# TR-1um cell library — generated by $APRTOOLS/apr/mklef.py
# source: TR-1um_STDCELL.gds

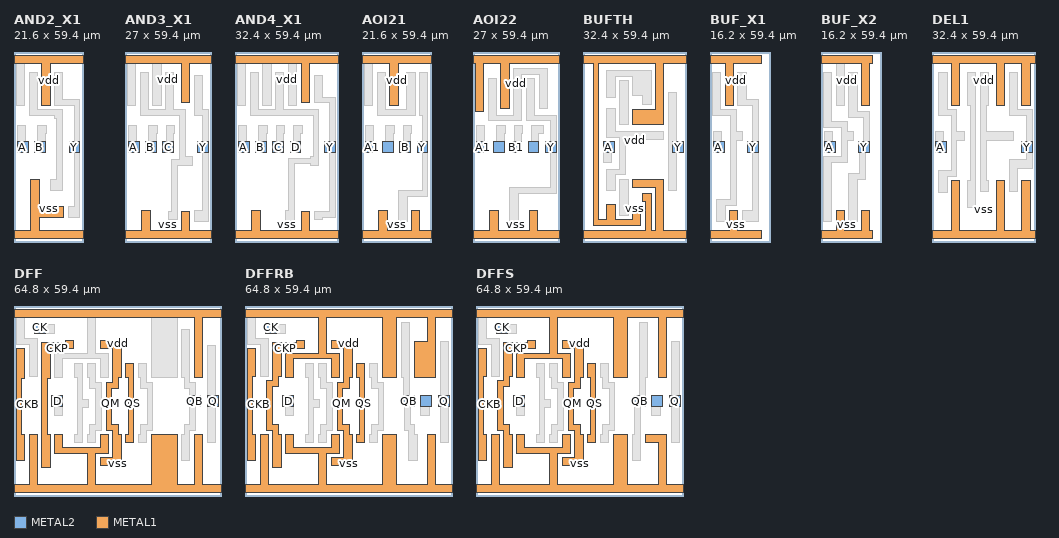
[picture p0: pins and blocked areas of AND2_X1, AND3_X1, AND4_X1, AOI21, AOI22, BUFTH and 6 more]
MACRO AND2_X1
  CLASS CORE ;
  FOREIGN AND2_X1 -0.000 -0.000 ;
  ORIGIN 0.000 0.000 ;
  SIZE 21.600 BY 59.400 ;
  SITE TR1UM ;
  SYMMETRY X Y ;
  PIN A
    DIRECTION INOUT ;
    USE SIGNAL ;
    PORT
      LAYER METAL2 ;
        RECT 1.000 28.000 4.400 31.400 ;
    END
  END A
  PIN B
    DIRECTION INOUT ;
    USE SIGNAL ;
    PORT
      LAYER METAL2 ;
        RECT 6.400 28.000 9.800 31.400 ;
    END
  END B
  PIN Y
    DIRECTION INOUT ;
    USE SIGNAL ;
    PORT
      LAYER METAL2 ;
        RECT 17.200 28.000 20.600 31.400 ;
    END
  END Y
  PIN vdd
    DIRECTION INOUT ;
    USE POWER ;
    SHAPE ABUTMENT ;
    PORT
      LAYER METAL1 ;
        POLYGON 11.300 42.700 11.300 55.700 21.600 55.700 21.600 58.300 0.000 58.300 0.000 55.700 8.700 55.700 8.700 42.700 ;
    END
  END vdd
  PIN vss
    DIRECTION INOUT ;
    USE GROUND ;
    SHAPE ABUTMENT ;
    PORT
      LAYER METAL1 ;
        POLYGON 0.000 1.100 21.600 1.100 21.600 3.700 7.900 3.700 7.900 7.700 15.500 7.700 15.500 11.100 7.900 11.100 7.900 19.600 5.300 19.600 5.300 3.700 0.000 3.700 ;
    END
  END vss
  OBS
    LAYER METAL1 ;
      RECT 0.700 42.700 3.300 55.700 ;
      POLYGON 20.600 44.600 15.300 44.600 15.300 52.900 12.700 52.900 12.700 42.700 18.800 42.700 18.800 31.400 20.600 31.400 ;
      POLYGON 15.200 41.300 7.300 41.300 7.300 52.900 4.700 52.900 4.700 39.500 12.600 39.500 12.600 38.700 13.400 38.700 13.400 19.600 11.500 19.600 11.500 16.200 15.200 16.200 ;
      POLYGON 9.800 33.900 10.100 33.900 10.100 36.500 7.500 36.500 7.500 31.400 9.800 31.400 ;
      RECT 1.000 31.400 3.600 36.500 ;
      POLYGON 16.900 11.100 16.900 7.700 20.600 7.700 20.600 28.000 18.800 28.000 18.800 11.100 ;
  END
END AND2_X1

MACRO AND3_X1
  CLASS CORE ;
  FOREIGN AND3_X1 -0.000 -0.000 ;
  ORIGIN 0.000 0.000 ;
  SIZE 27.000 BY 59.400 ;
  SITE TR1UM ;
  SYMMETRY X Y ;
  PIN A
    DIRECTION INOUT ;
    USE SIGNAL ;
    PORT
      LAYER METAL2 ;
        RECT 1.000 28.000 4.400 31.400 ;
    END
  END A
  PIN B
    DIRECTION INOUT ;
    USE SIGNAL ;
    PORT
      LAYER METAL2 ;
        RECT 6.400 28.000 9.800 31.400 ;
    END
  END B
  PIN C
    DIRECTION INOUT ;
    USE SIGNAL ;
    PORT
      LAYER METAL2 ;
        RECT 11.800 28.000 15.200 31.400 ;
    END
  END C
  PIN Y
    DIRECTION INOUT ;
    USE SIGNAL ;
    PORT
      LAYER METAL2 ;
        RECT 22.600 28.000 26.000 31.400 ;
    END
  END Y
  PIN vdd
    DIRECTION INOUT ;
    USE POWER ;
    SHAPE ABUTMENT ;
    PORT
      LAYER METAL1 ;
        POLYGON 20.300 43.500 20.300 55.700 27.000 55.700 27.000 58.300 0.000 58.300 0.000 55.700 17.700 55.700 17.700 43.500 ;
    END
  END vdd
  PIN vss
    DIRECTION INOUT ;
    USE GROUND ;
    SHAPE ABUTMENT ;
    PORT
      LAYER METAL1 ;
        POLYGON 0.000 1.100 27.000 1.100 27.000 3.700 20.300 3.700 20.300 9.500 17.700 9.500 17.700 3.700 7.900 3.700 7.900 9.900 5.300 9.900 5.300 3.700 0.000 3.700 ;
    END
  END vss
  OBS
    LAYER METAL1 ;
      RECT 8.700 42.700 11.300 55.700 ;
      RECT 0.700 42.700 3.300 55.700 ;
      POLYGON 16.300 24.000 21.200 24.000 21.200 26.600 18.900 26.600 18.900 41.300 15.300 41.300 15.300 52.900 12.700 52.900 12.700 41.300 7.300 41.300 7.300 52.900 4.700 52.900 4.700 39.500 17.100 39.500 17.100 25.800 14.500 25.800 14.500 9.500 13.700 9.500 13.700 6.900 16.300 6.900 ;
      POLYGON 26.000 41.300 24.300 41.300 24.300 52.100 21.700 52.100 21.700 39.500 24.200 39.500 24.200 31.400 26.000 31.400 ;
      RECT 1.000 31.400 3.600 36.500 ;
      POLYGON 9.800 33.900 10.100 33.900 10.100 36.500 7.500 36.500 7.500 31.400 9.800 31.400 ;
      POLYGON 15.200 33.900 15.500 33.900 15.500 36.500 12.900 36.500 12.900 31.400 15.200 31.400 ;
      POLYGON 21.700 9.900 21.700 6.500 26.000 6.500 26.000 28.000 24.200 28.000 24.200 9.900 ;
  END
END AND3_X1

MACRO AND4_X1
  CLASS CORE ;
  FOREIGN AND4_X1 -0.000 -0.000 ;
  ORIGIN 0.000 0.000 ;
  SIZE 32.400 BY 59.400 ;
  SITE TR1UM ;
  SYMMETRY X Y ;
  PIN A
    DIRECTION INOUT ;
    USE SIGNAL ;
    PORT
      LAYER METAL2 ;
        RECT 1.000 28.000 4.400 31.400 ;
    END
  END A
  PIN B
    DIRECTION INOUT ;
    USE SIGNAL ;
    PORT
      LAYER METAL2 ;
        RECT 6.400 28.000 9.800 31.400 ;
    END
  END B
  PIN C
    DIRECTION INOUT ;
    USE SIGNAL ;
    PORT
      LAYER METAL2 ;
        RECT 11.800 28.000 15.200 31.400 ;
    END
  END C
  PIN D
    DIRECTION INOUT ;
    USE SIGNAL ;
    PORT
      LAYER METAL2 ;
        RECT 17.200 28.000 20.600 31.400 ;
    END
  END D
  PIN Y
    DIRECTION INOUT ;
    USE SIGNAL ;
    PORT
      LAYER METAL2 ;
        RECT 28.000 28.000 31.400 31.400 ;
    END
  END Y
  PIN vdd
    DIRECTION INOUT ;
    USE POWER ;
    SHAPE ABUTMENT ;
    PORT
      LAYER METAL1 ;
        POLYGON 23.400 43.500 23.400 55.700 32.400 55.700 32.400 58.300 0.000 58.300 0.000 55.700 20.800 55.700 20.800 43.500 ;
    END
  END vdd
  PIN vss
    DIRECTION INOUT ;
    USE GROUND ;
    SHAPE ABUTMENT ;
    PORT
      LAYER METAL1 ;
        POLYGON 0.000 1.100 32.400 1.100 32.400 3.700 23.400 3.700 23.400 9.500 20.800 9.500 20.800 3.700 7.900 3.700 7.900 9.900 5.300 9.900 5.300 3.700 0.000 3.700 ;
    END
  END vss
  OBS
    LAYER METAL1 ;
      RECT 16.700 42.700 19.300 55.700 ;
      RECT 0.700 42.700 3.300 55.700 ;
      RECT 8.700 42.700 11.300 55.700 ;
      POLYGON 15.900 6.500 18.500 6.500 18.500 24.400 23.600 24.400 23.600 24.000 26.200 24.000 26.200 41.300 15.300 41.300 15.300 52.900 12.700 52.900 12.700 41.300 7.300 41.300 7.300 52.900 4.700 52.900 4.700 39.500 24.400 39.500 24.400 26.600 23.600 26.600 23.600 26.200 16.700 26.200 16.700 9.900 15.900 9.900 ;
      POLYGON 31.400 45.300 27.400 45.300 27.400 52.100 24.800 52.100 24.800 43.500 29.600 43.500 29.600 31.400 31.400 31.400 ;
      POLYGON 20.600 33.900 21.000 33.900 21.000 36.500 18.300 36.500 18.300 31.400 20.600 31.400 ;
      POLYGON 15.200 33.900 15.500 33.900 15.500 36.500 12.900 36.500 12.900 31.400 15.200 31.400 ;
      RECT 1.000 31.400 3.600 36.500 ;
      POLYGON 9.800 33.900 10.100 33.900 10.100 36.500 7.500 36.500 7.500 31.400 9.800 31.400 ;
      POLYGON 24.800 6.900 27.400 6.900 27.400 7.700 31.400 7.700 31.400 28.000 29.600 28.000 29.600 9.500 24.800 9.500 ;
  END
END AND4_X1

MACRO AOI21
  CLASS CORE ;
  FOREIGN AOI21 -0.000 -0.000 ;
  ORIGIN 0.000 0.000 ;
  SIZE 21.600 BY 59.400 ;
  SITE TR1UM ;
  SYMMETRY X Y ;
  PIN A1
    DIRECTION INOUT ;
    USE SIGNAL ;
    PORT
      LAYER METAL2 ;
        RECT 1.000 28.000 4.400 31.400 ;
    END
  END A1
  PIN A2
    DIRECTION INOUT ;
    USE SIGNAL ;
    PORT
      LAYER METAL2 ;
        RECT 6.400 28.000 9.800 31.400 ;
    END
  END A2
  PIN B
    DIRECTION INOUT ;
    USE SIGNAL ;
    PORT
      LAYER METAL2 ;
        RECT 11.800 28.000 15.200 31.400 ;
    END
  END B
  PIN Y
    DIRECTION INOUT ;
    USE SIGNAL ;
    PORT
      LAYER METAL2 ;
        RECT 17.200 28.000 20.600 31.400 ;
    END
  END Y
  PIN vdd
    DIRECTION INOUT ;
    USE POWER ;
    SHAPE ABUTMENT ;
    PORT
      LAYER METAL1 ;
        POLYGON 11.300 42.700 11.300 55.700 21.600 55.700 21.600 58.300 0.000 58.300 0.000 55.700 8.700 55.700 8.700 42.700 ;
    END
  END vdd
  PIN vss
    DIRECTION INOUT ;
    USE GROUND ;
    SHAPE ABUTMENT ;
    PORT
      LAYER METAL1 ;
        POLYGON 0.000 1.100 21.600 1.100 21.600 3.700 18.100 3.700 18.100 9.900 15.500 9.900 15.500 3.700 7.900 3.700 7.900 9.900 5.300 9.900 5.300 3.700 0.000 3.700 ;
    END
  END vss
  OBS
    LAYER METAL1 ;
      RECT 0.700 42.700 3.300 55.700 ;
      POLYGON 20.600 52.900 18.000 52.900 18.000 39.500 18.800 39.500 18.800 31.400 20.600 31.400 ;
      POLYGON 16.600 52.900 14.000 52.900 14.000 41.300 7.300 41.300 7.300 52.900 4.700 52.900 4.700 39.500 16.600 39.500 ;
      POLYGON 15.200 33.900 15.500 33.900 15.500 36.500 12.900 36.500 12.900 31.400 15.200 31.400 ;
      RECT 1.000 31.400 3.600 36.500 ;
      POLYGON 9.800 33.900 10.100 33.900 10.100 36.500 7.500 36.500 7.500 31.400 9.800 31.400 ;
      POLYGON 11.500 16.000 11.500 6.500 14.100 6.500 14.100 14.200 20.600 14.200 20.600 28.000 18.800 28.000 18.800 16.000 ;
  END
END AOI21

MACRO AOI22
  CLASS CORE ;
  FOREIGN AOI22 -0.000 -0.000 ;
  ORIGIN 0.000 0.000 ;
  SIZE 27.000 BY 59.400 ;
  SITE TR1UM ;
  SYMMETRY X Y ;
  PIN A1
    DIRECTION INOUT ;
    USE SIGNAL ;
    PORT
      LAYER METAL2 ;
        RECT 1.000 28.000 4.400 31.400 ;
    END
  END A1
  PIN A2
    DIRECTION INOUT ;
    USE SIGNAL ;
    PORT
      LAYER METAL2 ;
        RECT 6.400 28.000 9.800 31.400 ;
    END
  END A2
  PIN B1
    DIRECTION INOUT ;
    USE SIGNAL ;
    PORT
      LAYER METAL2 ;
        RECT 11.800 28.000 15.200 31.400 ;
    END
  END B1
  PIN B2
    DIRECTION INOUT ;
    USE SIGNAL ;
    PORT
      LAYER METAL2 ;
        RECT 17.200 28.000 20.600 31.400 ;
    END
  END B2
  PIN Y
    DIRECTION INOUT ;
    USE SIGNAL ;
    PORT
      LAYER METAL2 ;
        RECT 22.600 28.000 26.000 31.400 ;
    END
  END Y
  PIN vdd
    DIRECTION INOUT ;
    USE POWER ;
    SHAPE ABUTMENT ;
    PORT
      LAYER METAL1 ;
        POLYGON 3.300 40.900 3.300 55.700 8.700 55.700 8.700 41.700 11.300 41.700 11.300 55.700 27.000 55.700 27.000 58.300 0.000 58.300 0.000 55.700 0.700 55.700 0.700 40.900 ;
    END
  END vdd
  PIN vss
    DIRECTION INOUT ;
    USE GROUND ;
    SHAPE ABUTMENT ;
    PORT
      LAYER METAL1 ;
        POLYGON 0.000 1.100 27.000 1.100 27.000 3.700 20.300 3.700 20.300 9.900 17.700 9.900 17.700 3.700 7.900 3.700 7.900 9.900 5.300 9.900 5.300 3.700 0.000 3.700 ;
    END
  END vss
  OBS
    LAYER METAL1 ;
      POLYGON 15.300 52.500 20.700 52.500 20.700 41.700 23.300 41.700 23.300 54.300 12.700 54.300 12.700 39.700 7.300 39.700 7.300 51.100 4.700 51.100 4.700 37.900 15.300 37.900 ;
      POLYGON 16.700 51.100 16.700 37.900 24.200 37.900 24.200 31.400 26.000 31.400 26.000 39.700 19.300 39.700 19.300 51.100 ;
      POLYGON 20.600 33.900 22.100 33.900 22.100 36.500 18.300 36.500 18.300 31.400 20.600 31.400 ;
      RECT 1.000 31.400 3.600 36.500 ;
      POLYGON 9.800 33.900 10.100 33.900 10.100 36.500 7.500 36.500 7.500 31.400 9.800 31.400 ;
      POLYGON 15.200 33.900 15.500 33.900 15.500 36.500 12.900 36.500 12.900 31.400 15.200 31.400 ;
      POLYGON 11.500 17.000 11.500 6.500 14.100 6.500 14.100 15.200 26.000 15.200 26.000 28.000 24.200 28.000 24.200 17.000 ;
  END
END AOI22

MACRO BUFTH
  CLASS CORE ;
  FOREIGN BUFTH -0.000 -0.000 ;
  ORIGIN 0.000 0.000 ;
  SIZE 32.400 BY 59.400 ;
  SITE TR1UM ;
  SYMMETRY X Y ;
  PIN A
    DIRECTION INOUT ;
    USE SIGNAL ;
    PORT
      LAYER METAL2 ;
        RECT 6.400 28.000 9.800 31.400 ;
    END
  END A
  PIN Y
    DIRECTION INOUT ;
    USE SIGNAL ;
    PORT
      LAYER METAL2 ;
        RECT 28.000 28.000 31.400 31.400 ;
    END
  END Y
  PIN vdd
    DIRECTION INOUT ;
    USE POWER ;
    SHAPE ABUTMENT ;
    PORT
      LAYER METAL1 ;
        POLYGON 18.100 5.100 18.100 10.900 15.500 10.900 15.500 6.900 10.100 6.900 10.100 11.700 7.500 11.700 7.500 6.900 5.000 6.900 5.000 55.700 22.700 55.700 22.700 41.300 15.500 41.300 15.500 36.600 25.300 36.600 25.300 55.700 32.400 55.700 32.400 58.300 0.000 58.300 0.000 55.700 3.200 55.700 3.200 5.100 ;
    END
  END vdd
  PIN vss
    DIRECTION INOUT ;
    USE GROUND ;
    SHAPE ABUTMENT ;
    PORT
      LAYER METAL1 ;
        POLYGON 0.000 1.100 32.400 1.100 32.400 3.700 25.300 3.700 25.300 19.600 15.500 19.600 15.500 17.000 22.700 17.000 22.700 3.700 21.300 3.700 21.300 15.300 18.700 15.300 18.700 12.700 19.500 12.700 19.500 3.700 0.000 3.700 ;
    END
  END vss
  OBS
    LAYER METAL1 ;
      POLYGON 21.300 53.600 7.500 53.600 7.500 45.300 10.100 45.300 10.100 51.800 15.500 51.800 15.500 45.700 18.700 45.700 18.700 43.100 21.300 43.100 ;
      RECT 11.500 36.600 14.100 50.400 ;
      POLYGON 29.300 46.800 26.700 46.800 26.700 16.200 29.300 16.200 29.300 28.000 28.000 28.000 28.000 31.400 29.300 31.400 ;
      POLYGON 10.100 21.000 13.200 21.000 13.200 32.000 25.300 32.000 25.300 34.600 10.100 34.600 10.100 41.700 7.500 41.700 7.500 32.800 11.400 32.800 11.400 22.800 7.500 22.800 7.500 16.200 10.100 16.200 ;
      RECT 6.400 25.000 9.000 28.000 ;
      RECT 11.500 8.300 14.100 19.600 ;
  END
END BUFTH

MACRO BUF_X1
  CLASS CORE ;
  FOREIGN BUF_X1 -0.000 -0.000 ;
  ORIGIN 0.000 0.000 ;
  SIZE 16.200 BY 59.400 ;
  SITE TR1UM ;
  SYMMETRY X Y ;
  PIN A
    DIRECTION INOUT ;
    USE SIGNAL ;
    PORT
      LAYER METAL2 ;
        RECT 1.000 28.000 4.400 31.400 ;
    END
  END A
  PIN Y
    DIRECTION INOUT ;
    USE SIGNAL ;
    PORT
      LAYER METAL2 ;
        RECT 11.800 28.000 15.200 31.400 ;
    END
  END Y
  PIN vdd
    DIRECTION INOUT ;
    USE POWER ;
    SHAPE ABUTMENT ;
    PORT
      LAYER METAL1 ;
        POLYGON 7.300 42.700 7.300 55.700 16.200 55.700 16.200 58.300 0.000 58.300 0.000 55.700 4.700 55.700 4.700 42.700 ;
    END
  END vdd
  PIN vss
    DIRECTION INOUT ;
    USE GROUND ;
    SHAPE ABUTMENT ;
    PORT
      LAYER METAL1 ;
        POLYGON 0.000 1.100 16.200 1.100 16.200 3.700 8.700 3.700 8.700 9.900 6.100 9.900 6.100 3.700 0.000 3.700 ;
    END
  END vss
  OBS
    LAYER METAL1 ;
      POLYGON 15.200 44.500 11.300 44.500 11.300 52.900 8.700 52.900 8.700 42.700 13.400 42.700 13.400 31.400 15.200 31.400 ;
      POLYGON 4.700 11.500 8.300 11.500 8.300 31.800 10.100 31.800 10.100 34.400 8.300 34.400 8.300 41.300 3.300 41.300 3.300 52.900 0.700 52.900 0.700 39.500 6.500 39.500 6.500 13.300 2.100 13.300 2.100 6.500 4.700 6.500 ;
      RECT 1.000 31.400 3.600 34.400 ;
      POLYGON 10.100 9.900 10.100 6.500 15.200 6.500 15.200 28.000 13.400 28.000 13.400 9.900 ;
  END
END BUF_X1

MACRO BUF_X2
  CLASS CORE ;
  FOREIGN BUF_X2 -0.000 -0.000 ;
  ORIGIN 0.000 0.000 ;
  SIZE 16.200 BY 59.400 ;
  SITE TR1UM ;
  SYMMETRY X Y ;
  PIN A
    DIRECTION INOUT ;
    USE SIGNAL ;
    PORT
      LAYER METAL2 ;
        RECT 1.000 28.000 4.400 31.400 ;
    END
  END A
  PIN Y
    DIRECTION INOUT ;
    USE SIGNAL ;
    PORT
      LAYER METAL2 ;
        RECT 11.800 28.000 15.200 31.400 ;
    END
  END Y
  PIN vdd
    DIRECTION INOUT ;
    USE POWER ;
    SHAPE ABUTMENT ;
    PORT
      LAYER METAL1 ;
        POLYGON 15.300 42.700 15.300 55.700 16.200 55.700 16.200 58.300 0.000 58.300 0.000 55.700 12.700 55.700 12.700 42.700 ;
    END
  END vdd
  PIN vss
    DIRECTION INOUT ;
    USE GROUND ;
    SHAPE ABUTMENT ;
    PORT
      LAYER METAL1 ;
        POLYGON 0.000 1.100 16.200 1.100 16.200 3.700 15.300 3.700 15.300 9.900 12.700 9.900 12.700 3.700 7.300 3.700 7.300 9.900 4.700 9.900 4.700 3.700 0.000 3.700 ;
    END
  END vss
  OBS
    LAYER METAL1 ;
      RECT 4.700 42.700 7.300 55.700 ;
      POLYGON 15.200 40.800 11.300 40.800 11.300 52.900 8.700 52.900 8.700 39.000 13.400 39.000 13.400 31.400 15.200 31.400 ;
      POLYGON 3.300 24.800 8.300 24.800 8.300 31.800 10.100 31.800 10.100 34.400 8.300 34.400 8.300 37.600 3.300 37.600 3.300 52.900 0.700 52.900 0.700 35.800 6.500 35.800 6.500 26.600 0.700 26.600 0.700 6.500 3.300 6.500 ;
      RECT 1.000 31.400 3.600 34.400 ;
      POLYGON 8.700 21.400 8.700 6.500 11.300 6.500 11.300 19.600 13.800 19.600 13.800 28.000 12.000 28.000 12.000 21.400 ;
  END
END BUF_X2

MACRO DEL1
  CLASS CORE ;
  FOREIGN DEL1 -0.000 -0.000 ;
  ORIGIN 0.000 0.000 ;
  SIZE 32.400 BY 59.400 ;
  SITE TR1UM ;
  SYMMETRY X Y ;
  PIN A
    DIRECTION INOUT ;
    USE SIGNAL ;
    PORT
      LAYER METAL2 ;
        RECT 1.000 28.000 4.400 31.400 ;
    END
  END A
  PIN Y
    DIRECTION INOUT ;
    USE SIGNAL ;
    PORT
      LAYER METAL2 ;
        RECT 28.000 28.000 31.400 31.400 ;
    END
  END Y
  PIN vdd
    DIRECTION INOUT ;
    USE POWER ;
    SHAPE ABUTMENT ;
    PORT
      LAYER METAL1 ;
        POLYGON 8.700 55.700 20.100 55.700 20.100 42.700 22.700 42.700 22.700 55.700 28.100 55.700 28.100 42.700 30.700 42.700 30.700 55.700 32.400 55.700 32.400 58.300 0.000 58.300 0.000 55.700 6.100 55.700 6.100 42.700 8.700 42.700 ;
    END
  END vdd
  PIN vss
    DIRECTION INOUT ;
    USE GROUND ;
    SHAPE ABUTMENT ;
    PORT
      LAYER METAL1 ;
        POLYGON 32.400 3.700 30.700 3.700 30.700 19.100 28.100 19.100 28.100 3.700 22.700 3.700 22.700 19.100 20.100 19.100 20.100 3.700 8.700 3.700 8.700 19.100 6.100 19.100 6.100 3.700 0.000 3.700 0.000 1.100 32.400 1.100 ;
    END
  END vss
  OBS
    LAYER METAL1 ;
      POLYGON 31.400 41.300 26.700 41.300 26.700 52.900 24.100 52.900 24.100 39.500 29.600 39.500 29.600 31.400 31.400 31.400 ;
      POLYGON 13.700 52.900 11.100 52.900 11.100 42.700 11.900 42.700 11.900 19.100 11.100 19.100 11.100 10.700 13.700 10.700 ;
      POLYGON 17.700 19.100 16.900 19.100 16.900 31.800 25.500 31.800 25.500 34.400 16.900 34.400 16.900 42.700 17.700 42.700 17.700 52.900 15.100 52.900 15.100 15.700 17.700 15.700 ;
      POLYGON 4.700 20.500 7.800 20.500 7.800 31.800 10.100 31.800 10.100 34.400 7.800 34.400 7.800 41.300 4.700 41.300 4.700 52.900 2.100 52.900 2.100 39.500 6.000 39.500 6.000 22.300 2.100 22.300 2.100 15.500 4.700 15.500 ;
      RECT 1.000 31.400 3.600 34.400 ;
      POLYGON 24.100 25.800 24.100 15.700 26.700 15.700 26.700 22.900 31.400 22.900 31.400 28.000 29.600 28.000 29.600 25.800 ;
  END
END DEL1

MACRO DFF
  CLASS CORE ;
  FOREIGN DFF -0.000 -0.000 ;
  ORIGIN 0.000 0.000 ;
  SIZE 64.800 BY 59.400 ;
  SITE TR1UM ;
  SYMMETRY X Y ;
  PIN CK
    DIRECTION INOUT ;
    USE SIGNAL ;
    PORT
      LAYER METAL2 ;
        RECT 6.400 50.900 9.800 54.300 ;
    END
  END CK
  PIN CKB
    DIRECTION INOUT ;
    USE SIGNAL ;
    PORT
      LAYER METAL1 ;
        POLYGON 3.300 19.200 2.500 19.200 2.500 36.600 3.300 36.600 3.300 46.100 0.700 46.100 0.700 11.200 3.300 11.200 ;
    END
  END CKB
  PIN CKP
    DIRECTION INOUT ;
    USE SIGNAL ;
    PORT
      LAYER METAL1 ;
        POLYGON 11.300 19.200 10.500 19.200 10.500 22.400 10.400 22.400 10.400 34.300 10.500 34.300 10.500 36.600 11.300 36.600 11.300 46.100 18.700 46.100 18.700 48.700 16.100 48.700 16.100 47.900 8.700 47.900 8.700 36.100 8.600 36.100 8.600 20.600 8.700 20.600 8.700 9.000 11.300 9.000 ;
    END
  END CKP
  PIN D
    DIRECTION INOUT ;
    USE SIGNAL ;
    PORT
      LAYER METAL2 ;
        RECT 11.800 27.900 15.200 31.300 ;
    END
  END D
  PIN Q
    DIRECTION INOUT ;
    USE SIGNAL ;
    PORT
      LAYER METAL2 ;
        RECT 60.400 27.900 63.800 31.300 ;
    END
  END Q
  PIN QB
    DIRECTION INOUT ;
    USE SIGNAL ;
    PORT
      LAYER METAL2 ;
        RECT 55.000 27.900 58.400 31.300 ;
    END
  END QB
  PIN QM
    DIRECTION INOUT ;
    USE SIGNAL ;
    PORT
      LAYER METAL1 ;
        POLYGON 29.500 10.200 33.500 10.200 33.500 19.200 32.700 19.200 32.700 22.400 30.600 22.400 30.600 33.700 32.700 33.700 32.700 36.900 33.500 36.900 33.500 47.900 29.500 47.900 29.500 48.700 26.900 48.700 26.900 46.100 30.900 46.100 30.900 35.500 28.800 35.500 28.800 20.600 30.900 20.600 30.900 12.000 26.900 12.000 26.900 9.400 29.500 9.400 ;
    END
  END QM
  PIN QS
    DIRECTION INOUT ;
    USE SIGNAL ;
    PORT
      LAYER METAL1 ;
        POLYGON 37.500 27.700 39.300 27.700 39.300 30.300 37.500 30.300 37.500 41.500 34.900 41.500 34.900 36.900 35.700 36.900 35.700 19.200 34.900 19.200 34.900 16.600 37.500 16.600 ;
    END
  END QS
  PIN vdd
    DIRECTION INOUT ;
    USE POWER ;
    SHAPE ABUTMENT ;
    PORT
      LAYER METAL1 ;
        POLYGON 59.000 36.900 59.000 55.700 64.800 55.700 64.800 58.300 0.000 58.300 0.000 55.700 56.400 55.700 56.400 36.900 ;
    END
  END vdd
  PIN vss
    DIRECTION INOUT ;
    USE GROUND ;
    SHAPE ABUTMENT ;
    PORT
      LAYER METAL1 ;
        POLYGON 0.000 1.100 64.800 1.100 64.800 3.700 59.000 3.700 59.000 19.200 56.400 19.200 56.400 3.700 51.000 3.700 51.000 19.200 42.900 19.200 42.900 3.700 25.500 3.700 25.500 13.400 29.500 13.400 29.500 19.200 26.900 19.200 26.900 15.200 15.300 15.200 15.300 19.200 12.700 19.200 12.700 13.400 22.900 13.400 22.900 3.700 7.300 3.700 7.300 19.200 4.700 19.200 4.700 3.700 0.000 3.700 ;
    END
  END vss
  OBS
    LAYER METAL1 ;
      RECT 42.900 36.900 51.000 55.700 ;
      POLYGON 7.300 49.300 3.300 49.300 3.300 55.700 0.700 55.700 0.700 47.500 4.700 47.500 4.700 37.400 7.300 37.400 ;
      POLYGON 15.300 42.900 26.900 42.900 26.900 36.900 29.500 36.900 29.500 44.700 25.500 44.700 25.500 55.700 22.900 55.700 22.900 44.700 12.700 44.700 12.700 36.900 15.300 36.900 ;
      RECT 9.800 50.900 12.800 53.500 ;
      POLYGON 56.800 35.500 55.000 35.500 55.000 52.000 52.400 52.000 52.400 36.900 53.200 36.900 53.200 33.700 55.000 33.700 55.000 31.300 56.800 31.300 ;
      RECT 60.400 31.300 63.000 47.000 ;
      POLYGON 21.500 27.700 23.200 27.700 23.200 30.300 21.500 30.300 21.500 41.500 18.900 41.500 18.900 36.900 19.700 36.900 19.700 19.200 18.900 19.200 18.900 16.600 21.500 16.600 ;
      POLYGON 25.500 20.600 27.400 20.600 27.400 35.500 25.500 35.500 25.500 41.500 22.900 41.500 22.900 36.900 23.700 36.900 23.700 33.700 25.600 33.700 25.600 22.400 23.700 22.400 23.700 19.200 22.900 19.200 22.900 16.600 25.500 16.600 ;
      POLYGON 41.500 20.600 43.400 20.600 43.400 35.500 41.500 35.500 41.500 41.500 38.900 41.500 38.900 36.900 39.700 36.900 39.700 33.700 41.600 33.700 41.600 22.400 39.700 22.400 39.700 19.200 38.900 19.200 38.900 16.600 41.500 16.600 ;
      RECT 12.600 25.100 15.200 27.900 ;
      POLYGON 53.200 22.400 53.200 19.200 52.400 19.200 52.400 11.200 55.000 11.200 55.000 20.600 56.800 20.600 56.800 27.900 55.000 27.900 55.000 22.400 ;
      RECT 60.400 16.600 63.000 27.900 ;
  END
END DFF

MACRO DFFRB
  CLASS CORE ;
  FOREIGN DFFRB -0.000 -0.000 ;
  ORIGIN 0.000 0.000 ;
  SIZE 64.800 BY 59.400 ;
  SITE TR1UM ;
  SYMMETRY X Y ;
  PIN CK
    DIRECTION INOUT ;
    USE SIGNAL ;
    PORT
      LAYER METAL2 ;
        RECT 6.400 50.900 9.800 54.300 ;
    END
  END CK
  PIN CKB
    DIRECTION INOUT ;
    USE SIGNAL ;
    PORT
      LAYER METAL1 ;
        POLYGON 3.300 19.200 2.500 19.200 2.500 37.500 3.300 37.500 3.300 46.100 0.700 46.100 0.700 11.200 3.300 11.200 ;
    END
  END CKB
  PIN CKP
    DIRECTION INOUT ;
    USE SIGNAL ;
    PORT
      LAYER METAL1 ;
        POLYGON 10.500 19.200 10.500 22.400 8.600 22.400 8.600 34.300 10.500 34.300 10.500 37.500 11.300 37.500 11.300 46.100 18.700 46.100 18.700 48.700 16.100 48.700 16.100 47.900 8.700 47.900 8.700 36.100 6.800 36.100 6.800 20.600 8.700 20.600 8.700 9.000 11.300 9.000 11.300 19.200 ;
    END
  END CKP
  PIN D
    DIRECTION INOUT ;
    USE SIGNAL ;
    PORT
      LAYER METAL2 ;
        RECT 11.800 27.900 15.200 31.300 ;
    END
  END D
  PIN Q
    DIRECTION INOUT ;
    USE SIGNAL ;
    PORT
      LAYER METAL2 ;
        RECT 60.400 27.900 63.800 31.300 ;
    END
  END Q
  PIN QB
    DIRECTION INOUT ;
    USE SIGNAL ;
    PORT
      LAYER METAL2 ;
        RECT 49.600 27.900 53.000 31.300 ;
        RECT 49.600 27.900 53.000 31.300 ;
    END
  END QB
  PIN QM
    DIRECTION INOUT ;
    USE SIGNAL ;
    PORT
      LAYER METAL1 ;
        POLYGON 26.900 9.400 29.500 9.400 29.500 10.200 33.500 10.200 33.500 19.200 32.700 19.200 32.700 22.400 30.600 22.400 30.600 33.700 32.700 33.700 32.700 36.900 33.500 36.900 33.500 47.900 29.500 47.900 29.500 48.700 26.900 48.700 26.900 46.100 30.900 46.100 30.900 35.500 28.800 35.500 28.800 20.600 30.900 20.600 30.900 12.000 26.900 12.000 ;
    END
  END QM
  PIN QS
    DIRECTION INOUT ;
    USE SIGNAL ;
    PORT
      LAYER METAL1 ;
        POLYGON 37.500 27.700 39.300 27.700 39.300 30.300 37.500 30.300 37.500 41.500 34.900 41.500 34.900 36.900 35.700 36.900 35.700 19.200 34.900 19.200 34.900 16.600 37.500 16.600 ;
    END
  END QS
  PIN RSTB
    DIRECTION INOUT ;
    USE SIGNAL ;
    PORT
      LAYER METAL2 ;
        RECT 55.000 27.900 58.400 31.300 ;
    END
  END RSTB
  PIN vdd
    DIRECTION INOUT ;
    USE POWER ;
    SHAPE ABUTMENT ;
    PORT
      LAYER METAL1 ;
        POLYGON 57.000 48.400 52.900 48.400 52.900 36.900 59.600 36.900 59.600 55.700 64.800 55.700 64.800 58.300 0.000 58.300 0.000 55.700 22.900 55.700 22.900 44.700 12.700 44.700 12.700 36.900 15.300 36.900 15.300 42.900 26.900 42.900 26.900 36.900 29.500 36.900 29.500 44.700 25.500 44.700 25.500 55.700 42.900 55.700 42.900 36.900 47.500 36.900 47.500 55.700 57.000 55.700 ;
    END
  END vdd
  PIN vss
    DIRECTION INOUT ;
    USE GROUND ;
    SHAPE ABUTMENT ;
    PORT
      LAYER METAL1 ;
        POLYGON 0.000 1.100 64.800 1.100 64.800 3.700 59.600 3.700 59.600 19.200 57.000 19.200 57.000 3.700 47.500 3.700 47.500 19.200 42.900 19.200 42.900 3.700 25.500 3.700 25.500 13.400 29.500 13.400 29.500 19.200 26.900 19.200 26.900 15.200 15.300 15.200 15.300 19.200 12.700 19.200 12.700 13.400 22.900 13.400 22.900 3.700 7.300 3.700 7.300 19.200 4.700 19.200 4.700 3.700 0.000 3.700 ;
    END
  END vss
  OBS
    LAYER METAL1 ;
      POLYGON 7.300 49.300 3.300 49.300 3.300 55.700 0.700 55.700 0.700 47.500 4.700 47.500 4.700 37.500 7.300 37.500 ;
      POLYGON 51.500 54.200 48.900 54.200 48.900 36.900 49.700 36.900 49.700 31.300 51.500 31.300 ;
      RECT 9.800 50.900 12.800 53.500 ;
      RECT 61.000 31.300 63.600 48.400 ;
      POLYGON 21.500 27.700 23.200 27.700 23.200 30.300 21.500 30.300 21.500 41.500 18.900 41.500 18.900 36.900 19.700 36.900 19.700 19.200 18.900 19.200 18.900 16.600 21.500 16.600 ;
      POLYGON 25.500 20.600 27.400 20.600 27.400 35.500 25.500 35.500 25.500 41.500 22.900 41.500 22.900 36.900 23.700 36.900 23.700 33.700 25.600 33.700 25.600 22.400 23.700 22.400 23.700 19.200 22.900 19.200 22.900 16.600 25.500 16.600 ;
      POLYGON 41.500 20.600 43.400 20.600 43.400 35.500 41.500 35.500 41.500 41.500 38.900 41.500 38.900 36.900 39.700 36.900 39.700 33.700 41.600 33.700 41.600 22.400 39.700 22.400 39.700 19.200 38.900 19.200 38.900 16.600 41.500 16.600 ;
      RECT 12.600 25.100 15.200 27.900 ;
      RECT 55.000 25.100 57.600 27.900 ;
      POLYGON 51.200 20.600 51.200 11.200 53.800 11.200 53.800 19.200 53.000 19.200 53.000 22.400 51.600 22.400 51.600 27.900 49.800 27.900 49.800 20.600 ;
      RECT 61.000 16.600 63.600 27.900 ;
  END
END DFFRB

MACRO DFFS
  CLASS CORE ;
  FOREIGN DFFS -0.000 -0.000 ;
  ORIGIN 0.000 0.000 ;
  SIZE 64.800 BY 59.400 ;
  SITE TR1UM ;
  SYMMETRY X Y ;
  PIN CK
    DIRECTION INOUT ;
    USE SIGNAL ;
    PORT
      LAYER METAL2 ;
        RECT 6.400 50.900 9.800 54.300 ;
    END
  END CK
  PIN CKB
    DIRECTION INOUT ;
    USE SIGNAL ;
    PORT
      LAYER METAL1 ;
        POLYGON 3.300 19.200 2.500 19.200 2.500 37.500 3.300 37.500 3.300 46.100 0.700 46.100 0.700 11.200 3.300 11.200 ;
    END
  END CKB
  PIN CKP
    DIRECTION INOUT ;
    USE SIGNAL ;
    PORT
      LAYER METAL1 ;
        POLYGON 11.300 19.200 10.500 19.200 10.500 22.400 8.600 22.400 8.600 34.300 10.500 34.300 10.500 37.500 11.300 37.500 11.300 46.100 18.700 46.100 18.700 48.700 16.100 48.700 16.100 47.900 8.700 47.900 8.700 36.100 6.800 36.100 6.800 20.600 8.700 20.600 8.700 9.000 11.300 9.000 ;
    END
  END CKP
  PIN D
    DIRECTION INOUT ;
    USE SIGNAL ;
    PORT
      LAYER METAL2 ;
        RECT 11.800 27.900 15.200 31.300 ;
    END
  END D
  PIN Q
    DIRECTION INOUT ;
    USE SIGNAL ;
    PORT
      LAYER METAL2 ;
        RECT 60.400 27.900 63.800 31.300 ;
    END
  END Q
  PIN QB
    DIRECTION INOUT ;
    USE SIGNAL ;
    PORT
      LAYER METAL2 ;
        RECT 49.600 27.900 53.000 31.300 ;
        RECT 49.600 27.900 53.000 31.300 ;
    END
  END QB
  PIN QM
    DIRECTION INOUT ;
    USE SIGNAL ;
    PORT
      LAYER METAL1 ;
        POLYGON 29.500 10.200 33.500 10.200 33.500 19.200 32.700 19.200 32.700 22.400 30.600 22.400 30.600 33.700 32.700 33.700 32.700 36.900 33.500 36.900 33.500 47.900 29.500 47.900 29.500 48.700 26.900 48.700 26.900 46.100 30.900 46.100 30.900 35.500 28.800 35.500 28.800 20.600 30.900 20.600 30.900 12.000 26.900 12.000 26.900 9.400 29.500 9.400 ;
    END
  END QM
  PIN QS
    DIRECTION INOUT ;
    USE SIGNAL ;
    PORT
      LAYER METAL1 ;
        POLYGON 37.500 27.700 39.300 27.700 39.300 30.300 37.500 30.300 37.500 41.500 34.900 41.500 34.900 36.900 35.700 36.900 35.700 19.200 34.900 19.200 34.900 16.600 37.500 16.600 ;
    END
  END QS
  PIN SET
    DIRECTION INOUT ;
    USE SIGNAL ;
    PORT
      LAYER METAL2 ;
        RECT 55.000 27.900 58.400 31.300 ;
    END
  END SET
  PIN vdd
    DIRECTION INOUT ;
    USE POWER ;
    SHAPE ABUTMENT ;
    PORT
      LAYER METAL1 ;
        POLYGON 57.000 36.900 59.600 36.900 59.600 55.700 64.800 55.700 64.800 58.300 0.000 58.300 0.000 55.700 22.900 55.700 22.900 44.700 12.700 44.700 12.700 36.900 15.300 36.900 15.300 42.900 26.900 42.900 26.900 36.900 29.500 36.900 29.500 44.700 25.500 44.700 25.500 55.700 42.900 55.700 42.900 36.900 47.500 36.900 47.500 55.700 57.000 55.700 ;
    END
  END vdd
  PIN vss
    DIRECTION INOUT ;
    USE GROUND ;
    SHAPE ABUTMENT ;
    PORT
      LAYER METAL1 ;
        POLYGON 25.500 13.400 29.500 13.400 29.500 19.200 26.900 19.200 26.900 15.200 15.300 15.200 15.300 19.200 12.700 19.200 12.700 13.400 22.900 13.400 22.900 3.700 7.300 3.700 7.300 19.200 4.700 19.200 4.700 3.700 0.000 3.700 0.000 1.100 64.800 1.100 64.800 3.700 59.600 3.700 59.600 19.200 52.900 19.200 52.900 16.600 57.000 16.600 57.000 3.700 47.500 3.700 47.500 19.200 42.900 19.200 42.900 3.700 25.500 3.700 ;
    END
  END vss
  OBS
    LAYER METAL1 ;
      POLYGON 7.300 37.500 7.300 49.300 3.300 49.300 3.300 55.700 0.700 55.700 0.700 47.500 4.700 47.500 4.700 37.500 ;
      POLYGON 52.900 36.900 53.700 36.900 53.700 54.300 51.100 54.300 51.100 31.300 52.900 31.300 ;
      RECT 9.800 50.900 12.800 53.500 ;
      RECT 61.000 31.300 63.600 48.400 ;
      POLYGON 21.500 27.700 23.200 27.700 23.200 30.300 21.500 30.300 21.500 41.500 18.900 41.500 18.900 36.900 19.700 36.900 19.700 19.200 18.900 19.200 18.900 16.600 21.500 16.600 ;
      POLYGON 25.500 20.600 27.400 20.600 27.400 35.500 25.500 35.500 25.500 41.500 22.900 41.500 22.900 36.900 23.700 36.900 23.700 33.700 25.600 33.700 25.600 22.400 23.700 22.400 23.700 19.200 22.900 19.200 22.900 16.600 25.500 16.600 ;
      POLYGON 41.500 20.600 43.400 20.600 43.400 35.500 41.500 35.500 41.500 41.500 38.900 41.500 38.900 36.900 39.700 36.900 39.700 33.700 41.600 33.700 41.600 22.400 39.700 22.400 39.700 19.200 38.900 19.200 38.900 16.600 41.500 16.600 ;
      RECT 55.000 25.100 57.600 27.900 ;
      RECT 12.600 25.100 15.200 27.900 ;
      RECT 61.000 16.600 63.600 27.900 ;
      POLYGON 48.900 19.200 48.900 11.200 51.500 11.200 51.500 27.900 49.700 27.900 49.700 19.200 ;
  END
END DFFS

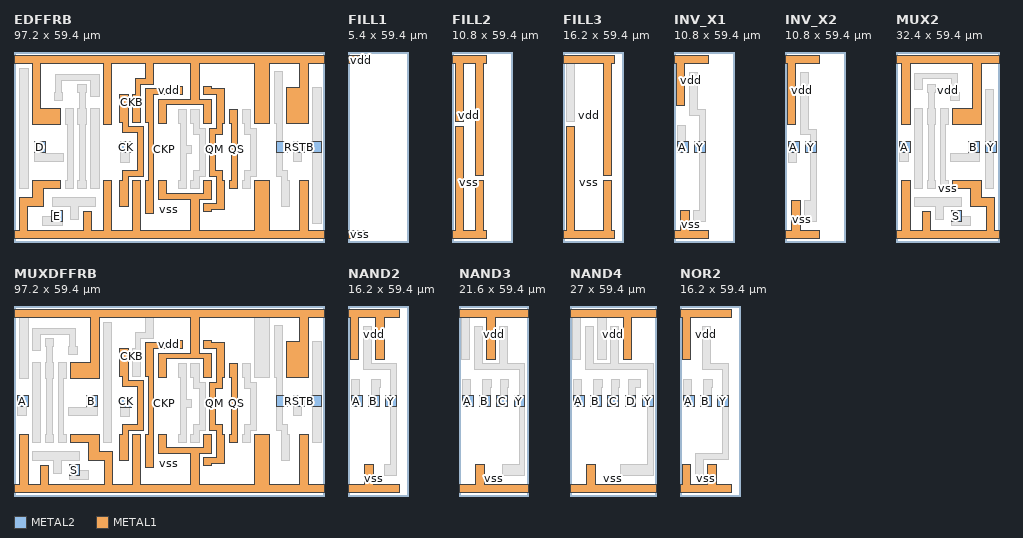
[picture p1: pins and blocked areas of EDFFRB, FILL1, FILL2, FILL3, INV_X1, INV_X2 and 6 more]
MACRO EDFFRB
  CLASS CORE ;
  FOREIGN EDFFRB -0.000 -0.000 ;
  ORIGIN 0.000 0.000 ;
  SIZE 97.200 BY 59.400 ;
  SITE TR1UM ;
  SYMMETRY X Y ;
  PIN CK
    DIRECTION INOUT ;
    USE SIGNAL ;
    PORT
      LAYER METAL2 ;
        RECT 33.400 27.900 36.800 31.300 ;
    END
  END CK
  PIN CKB
    DIRECTION INOUT ;
    USE SIGNAL ;
    PORT
      LAYER METAL1 ;
        POLYGON 35.700 20.600 40.500 20.600 40.500 36.100 35.700 36.100 35.700 46.100 33.100 46.100 33.100 37.500 33.900 37.500 33.900 34.300 38.700 34.300 38.700 22.400 33.900 22.400 33.900 19.200 33.100 19.200 33.100 11.200 35.700 11.200 ;
    END
  END CKB
  PIN CKP
    DIRECTION INOUT ;
    USE SIGNAL ;
    PORT
      LAYER METAL1 ;
        POLYGON 43.700 46.100 52.700 46.100 52.700 48.700 50.100 48.700 50.100 47.900 41.100 47.900 41.100 37.500 41.900 37.500 41.900 19.200 41.100 19.200 41.100 9.000 43.700 9.000 ;
    END
  END CKP
  PIN D
    DIRECTION INOUT ;
    USE SIGNAL ;
    PORT
      LAYER METAL2 ;
        RECT 6.400 27.900 9.800 31.300 ;
    END
  END D
  PIN E
    DIRECTION INOUT ;
    USE SIGNAL ;
    PORT
      LAYER METAL2 ;
        RECT 11.800 6.300 15.200 9.700 ;
    END
  END E
  PIN Q
    DIRECTION INOUT ;
    USE SIGNAL ;
    PORT
      LAYER METAL2 ;
        RECT 92.800 27.900 96.200 31.300 ;
    END
  END Q
  PIN QB
    DIRECTION INOUT ;
    USE SIGNAL ;
    PORT
      LAYER METAL2 ;
        RECT 82.000 27.900 85.400 31.300 ;
        RECT 82.000 27.900 85.400 31.300 ;
    END
  END QB
  PIN QM
    DIRECTION INOUT ;
    USE SIGNAL ;
    PORT
      LAYER METAL1 ;
        POLYGON 61.900 10.200 65.900 10.200 65.900 19.200 65.100 19.200 65.100 22.400 63.000 22.400 63.000 33.700 65.100 33.700 65.100 36.900 65.900 36.900 65.900 47.900 61.900 47.900 61.900 48.700 59.300 48.700 59.300 46.100 63.300 46.100 63.300 35.500 61.200 35.500 61.200 20.600 63.300 20.600 63.300 12.000 59.300 12.000 59.300 9.400 61.900 9.400 ;
    END
  END QM
  PIN QS
    DIRECTION INOUT ;
    USE SIGNAL ;
    PORT
      LAYER METAL1 ;
        POLYGON 69.900 27.700 71.700 27.700 71.700 30.300 69.900 30.300 69.900 41.500 67.300 41.500 67.300 36.900 68.100 36.900 68.100 19.200 67.300 19.200 67.300 16.600 69.900 16.600 ;
    END
  END QS
  PIN RSTB
    DIRECTION INOUT ;
    USE SIGNAL ;
    PORT
      LAYER METAL2 ;
        RECT 87.400 27.900 90.800 31.300 ;
    END
  END RSTB
  PIN vdd
    DIRECTION INOUT ;
    USE POWER ;
    SHAPE ABUTMENT ;
    PORT
      LAYER METAL1 ;
        POLYGON 14.600 41.700 8.400 41.700 8.400 55.700 28.000 55.700 28.000 36.700 30.600 36.700 30.600 55.700 41.100 55.700 41.100 51.100 37.900 51.100 37.900 46.100 37.100 46.100 37.100 37.500 39.700 37.500 39.700 49.300 43.700 49.300 43.700 55.700 55.300 55.700 55.300 44.700 45.100 44.700 45.100 36.900 47.700 36.900 47.700 42.900 59.300 42.900 59.300 36.900 61.900 36.900 61.900 44.700 57.900 44.700 57.900 55.700 75.300 55.700 75.300 36.900 79.900 36.900 79.900 55.700 89.400 55.700 89.400 48.400 85.300 48.400 85.300 36.900 92.000 36.900 92.000 55.700 97.200 55.700 97.200 58.300 0.000 58.300 0.000 55.700 5.800 55.700 5.800 36.700 14.600 36.700 ;
    END
  END vdd
  PIN vss
    DIRECTION INOUT ;
    USE GROUND ;
    SHAPE ABUTMENT ;
    PORT
      LAYER METAL1 ;
        POLYGON 97.200 3.700 92.000 3.700 92.000 19.200 89.400 19.200 89.400 3.700 79.900 3.700 79.900 19.200 75.300 19.200 75.300 3.700 57.900 3.700 57.900 13.400 61.900 13.400 61.900 19.200 59.300 19.200 59.300 15.200 47.700 15.200 47.700 19.200 45.100 19.200 45.100 13.400 55.300 13.400 55.300 3.700 39.700 3.700 39.700 19.200 37.100 19.200 37.100 3.700 30.600 3.700 30.600 19.300 28.000 19.300 28.000 3.700 24.200 3.700 24.200 9.500 21.600 9.500 21.600 3.700 4.200 3.700 4.200 11.200 9.100 11.200 9.100 16.600 14.600 16.600 14.600 19.300 5.800 19.300 5.800 13.800 1.600 13.800 1.600 3.700 0.000 3.700 0.000 1.100 97.200 1.100 ;
    END
  END vss
  OBS
    LAYER METAL1 ;
      RECT 1.800 16.600 4.400 54.300 ;
      POLYGON 83.900 53.400 81.300 53.400 81.300 36.900 82.100 36.900 82.100 31.300 83.900 31.300 ;
      POLYGON 15.300 46.800 14.900 46.800 14.900 50.600 24.000 50.600 24.000 45.600 26.600 45.600 26.600 52.400 13.100 52.400 13.100 46.800 12.700 46.800 12.700 44.200 15.300 44.200 ;
      POLYGON 22.600 19.300 22.200 19.300 22.200 36.700 22.600 36.700 22.600 41.700 22.200 41.700 22.200 46.600 22.600 46.600 22.600 49.200 20.000 49.200 20.000 46.600 20.400 46.600 20.400 41.700 20.000 41.700 20.000 36.700 20.400 36.700 20.400 19.300 20.000 19.300 20.000 16.600 22.600 16.600 ;
      RECT 93.400 31.300 96.000 48.400 ;
      RECT 24.000 16.600 26.600 41.700 ;
      POLYGON 18.600 41.700 16.000 41.700 16.000 36.700 16.800 36.700 16.800 19.300 16.000 19.300 16.000 16.600 18.600 16.600 ;
      POLYGON 53.900 27.700 55.600 27.700 55.600 30.300 53.900 30.300 53.900 41.500 51.300 41.500 51.300 36.900 52.100 36.900 52.100 19.200 51.300 19.200 51.300 16.600 53.900 16.600 ;
      POLYGON 57.900 20.600 59.800 20.600 59.800 35.500 57.900 35.500 57.900 41.500 55.300 41.500 55.300 36.900 56.100 36.900 56.100 33.700 58.000 33.700 58.000 22.400 56.100 22.400 56.100 19.200 55.300 19.200 55.300 16.600 57.900 16.600 ;
      POLYGON 73.900 20.600 75.800 20.600 75.800 35.500 73.900 35.500 73.900 41.500 71.300 41.500 71.300 36.900 72.100 36.900 72.100 33.700 74.000 33.700 74.000 22.400 72.100 22.400 72.100 19.200 71.300 19.200 71.300 16.600 73.900 16.600 ;
      RECT 87.400 25.100 90.000 27.900 ;
      RECT 33.400 24.700 36.000 27.900 ;
      POLYGON 15.400 27.700 9.800 27.700 9.800 27.900 6.400 27.900 6.400 25.100 15.400 25.100 ;
      POLYGON 20.200 11.200 25.400 11.200 25.400 13.800 12.000 13.800 12.000 11.200 17.600 11.200 17.600 6.900 20.200 6.900 ;
      POLYGON 11.800 6.300 11.800 7.900 9.000 7.900 9.000 5.300 15.200 5.300 15.200 6.300 ;
      RECT 93.400 5.800 96.000 27.900 ;
      POLYGON 83.600 20.600 83.600 11.200 86.200 11.200 86.200 19.200 85.400 19.200 85.400 22.400 84.000 22.400 84.000 27.900 82.200 27.900 82.200 20.600 ;
  END
END EDFFRB

MACRO FILL1
  CLASS CORE SPACER ;
  FOREIGN FILL1 -0.000 -0.000 ;
  ORIGIN 0.000 0.000 ;
  SIZE 5.400 BY 59.400 ;
  SITE TR1UM ;
  SYMMETRY X Y ;
  PIN vdd
    DIRECTION INOUT ;
    USE POWER ;
    SHAPE ABUTMENT ;
    PORT
      LAYER METAL1 ;
        RECT 0.000 55.700 5.400 58.300 ;
    END
  END vdd
  PIN vss
    DIRECTION INOUT ;
    USE GROUND ;
    SHAPE ABUTMENT ;
    PORT
      LAYER METAL1 ;
        RECT 0.000 1.100 5.400 3.700 ;
    END
  END vss
END FILL1

MACRO FILL2
  CLASS CORE SPACER ;
  FOREIGN FILL2 -0.000 -0.000 ;
  ORIGIN 0.000 0.000 ;
  SIZE 10.800 BY 59.400 ;
  SITE TR1UM ;
  SYMMETRY X Y ;
  PIN vdd
    DIRECTION INOUT ;
    USE POWER ;
    SHAPE ABUTMENT ;
    PORT
      LAYER METAL1 ;
        POLYGON 3.600 37.700 3.600 55.700 7.200 55.700 7.200 20.700 9.800 20.700 9.800 55.700 10.800 55.700 10.800 58.300 0.000 58.300 0.000 55.700 1.000 55.700 1.000 37.700 ;
    END
  END vdd
  PIN vss
    DIRECTION INOUT ;
    USE GROUND ;
    SHAPE ABUTMENT ;
    PORT
      LAYER METAL1 ;
        POLYGON 0.000 1.100 10.800 1.100 10.800 3.700 9.800 3.700 9.800 19.100 7.200 19.100 7.200 3.700 3.600 3.700 3.600 36.100 1.000 36.100 1.000 3.700 0.000 3.700 ;
    END
  END vss
END FILL2

MACRO FILL3
  CLASS CORE SPACER ;
  FOREIGN FILL3 -0.000 -0.000 ;
  ORIGIN 0.000 0.000 ;
  SIZE 16.200 BY 59.400 ;
  SITE TR1UM ;
  SYMMETRY X Y ;
  PIN vdd
    DIRECTION INOUT ;
    USE POWER ;
    SHAPE ABUTMENT ;
    PORT
      LAYER METAL1 ;
        POLYGON 15.200 20.700 15.200 55.700 16.200 55.700 16.200 58.300 0.000 58.300 0.000 55.700 12.600 55.700 12.600 20.700 ;
    END
  END vdd
  PIN vss
    DIRECTION INOUT ;
    USE GROUND ;
    SHAPE ABUTMENT ;
    PORT
      LAYER METAL1 ;
        POLYGON 0.000 1.100 16.200 1.100 16.200 3.700 15.200 3.700 15.200 19.100 12.600 19.100 12.600 3.700 3.600 3.700 3.600 36.100 1.000 36.100 1.000 3.700 0.000 3.700 ;
    END
  END vss
  OBS
    LAYER METAL1 ;
      RECT 1.000 37.700 3.600 55.700 ;
  END
END FILL3

MACRO INV_X1
  CLASS CORE ;
  FOREIGN INV_X1 -0.000 -0.000 ;
  ORIGIN 0.000 0.000 ;
  SIZE 10.800 BY 59.400 ;
  SITE TR1UM ;
  SYMMETRY X Y ;
  PIN A
    DIRECTION INOUT ;
    USE SIGNAL ;
    PORT
      LAYER METAL2 ;
        RECT 1.000 28.000 4.400 31.400 ;
    END
  END A
  PIN Y
    DIRECTION INOUT ;
    USE SIGNAL ;
    PORT
      LAYER METAL2 ;
        RECT 6.400 28.000 9.800 31.400 ;
    END
  END Y
  PIN vdd
    DIRECTION INOUT ;
    USE POWER ;
    SHAPE ABUTMENT ;
    PORT
      LAYER METAL1 ;
        POLYGON 3.300 42.700 3.300 55.700 10.800 55.700 10.800 58.300 0.000 58.300 0.000 55.700 0.700 55.700 0.700 42.700 ;
    END
  END vdd
  PIN vss
    DIRECTION INOUT ;
    USE GROUND ;
    SHAPE ABUTMENT ;
    PORT
      LAYER METAL1 ;
        POLYGON 0.000 1.100 10.800 1.100 10.800 3.700 4.700 3.700 4.700 9.900 2.100 9.900 2.100 3.700 0.000 3.700 ;
    END
  END vss
  OBS
    LAYER METAL1 ;
      POLYGON 8.000 9.900 6.100 9.900 6.100 6.500 9.800 6.500 9.800 28.000 8.000 28.000 ;
      RECT 1.000 31.400 3.600 36.500 ;
      POLYGON 9.800 41.300 7.300 41.300 7.300 52.900 4.700 52.900 4.700 39.500 8.000 39.500 8.000 31.400 9.800 31.400 ;
  END
END INV_X1

MACRO INV_X2
  CLASS CORE ;
  FOREIGN INV_X2 -0.000 -0.000 ;
  ORIGIN 0.000 0.000 ;
  SIZE 10.800 BY 59.400 ;
  SITE TR1UM ;
  SYMMETRY X Y ;
  PIN A
    DIRECTION INOUT ;
    USE SIGNAL ;
    PORT
      LAYER METAL2 ;
        RECT 1.000 28.000 4.400 31.400 ;
    END
  END A
  PIN Y
    DIRECTION INOUT ;
    USE SIGNAL ;
    PORT
      LAYER METAL2 ;
        RECT 6.400 28.000 9.800 31.400 ;
    END
  END Y
  PIN vdd
    DIRECTION INOUT ;
    USE POWER ;
    SHAPE ABUTMENT ;
    PORT
      LAYER METAL1 ;
        POLYGON 3.300 36.700 3.300 55.700 10.800 55.700 10.800 58.300 0.000 58.300 0.000 55.700 0.700 55.700 0.700 36.700 ;
    END
  END vdd
  PIN vss
    DIRECTION INOUT ;
    USE GROUND ;
    SHAPE ABUTMENT ;
    PORT
      LAYER METAL1 ;
        POLYGON 0.000 1.100 10.800 1.100 10.800 3.700 4.700 3.700 4.700 13.100 2.100 13.100 2.100 3.700 0.000 3.700 ;
    END
  END vss
  OBS
    LAYER METAL1 ;
      POLYGON 9.800 35.300 7.300 35.300 7.300 52.900 4.700 52.900 4.700 33.500 8.000 33.500 8.000 31.400 9.800 31.400 ;
      RECT 1.000 25.000 3.600 28.000 ;
      POLYGON 6.100 13.100 6.100 6.500 9.800 6.500 9.800 28.000 8.000 28.000 8.000 13.100 ;
  END
END INV_X2

MACRO MUX2
  CLASS CORE ;
  FOREIGN MUX2 -0.000 -0.000 ;
  ORIGIN 0.000 0.000 ;
  SIZE 32.400 BY 59.400 ;
  SITE TR1UM ;
  SYMMETRY X Y ;
  PIN A
    DIRECTION INOUT ;
    USE SIGNAL ;
    PORT
      LAYER METAL2 ;
        RECT 1.000 27.900 4.400 31.300 ;
    END
  END A
  PIN B
    DIRECTION INOUT ;
    USE SIGNAL ;
    PORT
      LAYER METAL2 ;
        RECT 22.600 27.900 26.000 31.300 ;
    END
  END B
  PIN S
    DIRECTION INOUT ;
    USE SIGNAL ;
    PORT
      LAYER METAL2 ;
        RECT 17.200 6.300 20.600 9.700 ;
    END
  END S
  PIN Y
    DIRECTION INOUT ;
    USE SIGNAL ;
    PORT
      LAYER METAL2 ;
        RECT 28.000 27.900 31.400 31.300 ;
    END
  END Y
  PIN vdd
    DIRECTION INOUT ;
    USE POWER ;
    SHAPE ABUTMENT ;
    PORT
      LAYER METAL1 ;
        POLYGON 4.400 36.700 4.400 55.700 24.000 55.700 24.000 41.700 17.800 41.700 17.800 36.700 26.600 36.700 26.600 55.700 32.400 55.700 32.400 58.300 0.000 58.300 0.000 55.700 1.800 55.700 1.800 36.700 ;
    END
  END vdd
  PIN vss
    DIRECTION INOUT ;
    USE GROUND ;
    SHAPE ABUTMENT ;
    PORT
      LAYER METAL1 ;
        POLYGON 0.000 1.100 32.400 1.100 32.400 3.700 30.800 3.700 30.800 13.800 26.600 13.800 26.600 19.300 17.800 19.300 17.800 16.600 23.300 16.600 23.300 11.200 28.200 11.200 28.200 3.700 10.800 3.700 10.800 9.500 8.200 9.500 8.200 3.700 4.400 3.700 4.400 19.300 1.800 19.300 1.800 3.700 0.000 3.700 ;
    END
  END vss
  OBS
    LAYER METAL1 ;
      POLYGON 19.700 46.800 19.300 46.800 19.300 52.800 5.800 52.800 5.800 47.800 8.400 47.800 8.400 51.000 17.500 51.000 17.500 46.800 17.100 46.800 17.100 44.200 19.700 44.200 ;
      POLYGON 12.400 19.300 12.000 19.300 12.000 36.700 12.400 36.700 12.400 41.700 12.000 41.700 12.000 46.600 12.400 46.600 12.400 49.200 9.800 49.200 9.800 46.600 10.200 46.600 10.200 41.700 9.800 41.700 9.800 36.700 10.200 36.700 10.200 19.300 9.800 19.300 9.800 16.600 12.400 16.600 ;
      RECT 28.000 31.300 30.600 47.600 ;
      RECT 5.800 16.600 8.400 41.700 ;
      POLYGON 16.400 19.300 15.600 19.300 15.600 36.700 16.400 36.700 16.400 41.700 13.800 41.700 13.800 16.600 16.400 16.600 ;
      POLYGON 26.000 27.900 22.600 27.900 22.600 27.700 17.000 27.700 17.000 25.100 26.000 25.100 ;
      RECT 1.200 25.100 3.800 27.900 ;
      POLYGON 14.800 11.200 20.400 11.200 20.400 13.800 5.800 13.800 5.800 11.200 12.200 11.200 12.200 6.900 14.800 6.900 ;
      POLYGON 17.200 6.300 17.200 5.300 23.400 5.300 23.400 7.900 20.600 7.900 20.600 6.300 ;
      RECT 28.000 16.600 30.600 27.900 ;
  END
END MUX2

MACRO MUXDFFRB
  CLASS CORE ;
  FOREIGN MUXDFFRB -0.000 -0.000 ;
  ORIGIN 0.000 0.000 ;
  SIZE 97.200 BY 59.400 ;
  SITE TR1UM ;
  SYMMETRY X Y ;
  PIN A
    DIRECTION INOUT ;
    USE SIGNAL ;
    PORT
      LAYER METAL2 ;
        RECT 1.000 27.900 4.400 31.300 ;
    END
  END A
  PIN B
    DIRECTION INOUT ;
    USE SIGNAL ;
    PORT
      LAYER METAL2 ;
        RECT 22.600 27.900 26.000 31.300 ;
    END
  END B
  PIN CK
    DIRECTION INOUT ;
    USE SIGNAL ;
    PORT
      LAYER METAL2 ;
        RECT 33.400 27.700 36.800 31.100 ;
    END
  END CK
  PIN CKB
    DIRECTION INOUT ;
    USE SIGNAL ;
    PORT
      LAYER METAL1 ;
        POLYGON 33.900 34.300 38.700 34.300 38.700 22.400 33.900 22.400 33.900 19.200 33.100 19.200 33.100 11.200 35.700 11.200 35.700 20.600 40.500 20.600 40.500 36.100 35.700 36.100 35.700 46.100 33.100 46.100 33.100 37.500 33.900 37.500 ;
    END
  END CKB
  PIN CKP
    DIRECTION INOUT ;
    USE SIGNAL ;
    PORT
      LAYER METAL1 ;
        POLYGON 41.900 19.200 41.100 19.200 41.100 9.000 43.700 9.000 43.700 46.100 52.700 46.100 52.700 48.700 50.100 48.700 50.100 47.900 41.100 47.900 41.100 37.500 41.900 37.500 ;
    END
  END CKP
  PIN Q
    DIRECTION INOUT ;
    USE SIGNAL ;
    PORT
      LAYER METAL2 ;
        RECT 92.800 27.900 96.200 31.300 ;
    END
  END Q
  PIN QB
    DIRECTION INOUT ;
    USE SIGNAL ;
    PORT
      LAYER METAL2 ;
        RECT 82.000 27.900 85.400 31.300 ;
        RECT 82.000 27.900 85.400 31.300 ;
    END
  END QB
  PIN QM
    DIRECTION INOUT ;
    USE SIGNAL ;
    PORT
      LAYER METAL1 ;
        POLYGON 61.900 10.200 65.900 10.200 65.900 19.200 65.100 19.200 65.100 22.400 63.000 22.400 63.000 33.700 65.100 33.700 65.100 36.900 65.900 36.900 65.900 47.900 61.900 47.900 61.900 48.700 59.300 48.700 59.300 46.100 63.300 46.100 63.300 35.500 61.200 35.500 61.200 20.600 63.300 20.600 63.300 12.000 59.300 12.000 59.300 9.400 61.900 9.400 ;
    END
  END QM
  PIN QS
    DIRECTION INOUT ;
    USE SIGNAL ;
    PORT
      LAYER METAL1 ;
        POLYGON 69.900 27.700 71.700 27.700 71.700 30.300 69.900 30.300 69.900 41.500 67.300 41.500 67.300 36.900 68.100 36.900 68.100 19.200 67.300 19.200 67.300 16.600 69.900 16.600 ;
    END
  END QS
  PIN RSTB
    DIRECTION INOUT ;
    USE SIGNAL ;
    PORT
      LAYER METAL2 ;
        RECT 87.400 27.900 90.800 31.300 ;
    END
  END RSTB
  PIN S
    DIRECTION INOUT ;
    USE SIGNAL ;
    PORT
      LAYER METAL2 ;
        RECT 17.200 6.300 20.600 9.700 ;
    END
  END S
  PIN vdd
    DIRECTION INOUT ;
    USE POWER ;
    SHAPE ABUTMENT ;
    PORT
      LAYER METAL1 ;
        POLYGON 89.400 48.400 85.300 48.400 85.300 36.900 92.000 36.900 92.000 55.700 97.200 55.700 97.200 58.300 0.000 58.300 0.000 55.700 24.000 55.700 24.000 41.700 17.800 41.700 17.800 36.700 26.600 36.700 26.600 55.700 55.300 55.700 55.300 44.700 45.100 44.700 45.100 36.900 47.700 36.900 47.700 42.900 59.300 42.900 59.300 36.900 61.900 36.900 61.900 44.700 57.900 44.700 57.900 55.700 89.400 55.700 ;
    END
  END vdd
  PIN vss
    DIRECTION INOUT ;
    USE GROUND ;
    SHAPE ABUTMENT ;
    PORT
      LAYER METAL1 ;
        POLYGON 0.000 1.100 97.200 1.100 97.200 3.700 92.000 3.700 92.000 19.200 89.400 19.200 89.400 3.700 79.900 3.700 79.900 19.200 75.300 19.200 75.300 3.700 57.900 3.700 57.900 13.400 61.900 13.400 61.900 19.200 59.300 19.200 59.300 15.200 47.700 15.200 47.700 19.200 45.100 19.200 45.100 13.400 55.300 13.400 55.300 3.700 39.700 3.700 39.700 19.200 37.100 19.200 37.100 3.700 30.800 3.700 30.800 13.800 26.600 13.800 26.600 19.300 17.800 19.300 17.800 16.600 23.300 16.600 23.300 11.200 28.200 11.200 28.200 3.700 10.800 3.700 10.800 9.500 8.200 9.500 8.200 3.700 4.400 3.700 4.400 19.300 1.800 19.300 1.800 3.700 0.000 3.700 ;
    END
  END vss
  OBS
    LAYER METAL1 ;
      RECT 1.800 36.700 4.400 55.700 ;
      RECT 75.300 36.900 79.900 55.700 ;
      POLYGON 39.700 49.300 43.700 49.300 43.700 55.700 41.100 55.700 41.100 51.100 37.900 51.100 37.900 46.100 37.100 46.100 37.100 37.500 39.700 37.500 ;
      RECT 28.000 16.600 30.600 54.300 ;
      POLYGON 83.900 53.400 81.300 53.400 81.300 36.900 82.100 36.900 82.100 31.300 83.900 31.300 ;
      POLYGON 19.700 46.800 19.300 46.800 19.300 52.400 5.800 52.400 5.800 45.600 8.400 45.600 8.400 50.600 17.500 50.600 17.500 46.800 17.100 46.800 17.100 44.200 19.700 44.200 ;
      POLYGON 12.400 19.300 12.000 19.300 12.000 36.700 12.400 36.700 12.400 41.700 12.000 41.700 12.000 46.600 12.400 46.600 12.400 49.200 9.800 49.200 9.800 46.600 10.200 46.600 10.200 41.700 9.800 41.700 9.800 36.700 10.200 36.700 10.200 19.300 9.800 19.300 9.800 16.600 12.400 16.600 ;
      RECT 93.400 31.300 96.000 48.400 ;
      POLYGON 16.400 19.300 15.600 19.300 15.600 36.700 16.400 36.700 16.400 41.700 13.800 41.700 13.800 16.600 16.400 16.600 ;
      RECT 5.800 16.600 8.400 41.700 ;
      POLYGON 53.900 27.700 55.600 27.700 55.600 30.300 53.900 30.300 53.900 41.500 51.300 41.500 51.300 36.900 52.100 36.900 52.100 19.200 51.300 19.200 51.300 16.600 53.900 16.600 ;
      POLYGON 57.900 20.600 59.800 20.600 59.800 35.500 57.900 35.500 57.900 41.500 55.300 41.500 55.300 36.900 56.100 36.900 56.100 33.700 58.000 33.700 58.000 22.400 56.100 22.400 56.100 19.200 55.300 19.200 55.300 16.600 57.900 16.600 ;
      POLYGON 73.900 20.600 75.800 20.600 75.800 35.500 73.900 35.500 73.900 41.500 71.300 41.500 71.300 36.900 72.100 36.900 72.100 33.700 74.000 33.700 74.000 22.400 72.100 22.400 72.100 19.200 71.300 19.200 71.300 16.600 73.900 16.600 ;
      RECT 1.200 25.100 3.800 27.900 ;
      POLYGON 22.600 27.900 22.600 27.700 17.000 27.700 17.000 25.100 26.000 25.100 26.000 27.900 ;
      RECT 87.400 25.100 90.000 27.900 ;
      RECT 33.400 24.700 36.000 27.700 ;
      POLYGON 14.800 11.200 20.400 11.200 20.400 13.800 5.800 13.800 5.800 11.200 12.200 11.200 12.200 6.900 14.800 6.900 ;
      POLYGON 17.200 6.300 17.200 5.300 23.400 5.300 23.400 7.900 20.600 7.900 20.600 6.300 ;
      POLYGON 83.600 20.600 83.600 11.200 86.200 11.200 86.200 19.200 85.400 19.200 85.400 22.400 84.000 22.400 84.000 27.900 82.200 27.900 82.200 20.600 ;
      RECT 93.400 16.600 96.000 27.900 ;
  END
END MUXDFFRB

MACRO NAND2
  CLASS CORE ;
  FOREIGN NAND2 -0.000 -0.000 ;
  ORIGIN 0.000 0.000 ;
  SIZE 16.200 BY 59.400 ;
  SITE TR1UM ;
  SYMMETRY X Y ;
  PIN A
    DIRECTION INOUT ;
    USE SIGNAL ;
    PORT
      LAYER METAL2 ;
        RECT 1.000 28.000 4.400 31.400 ;
    END
  END A
  PIN B
    DIRECTION INOUT ;
    USE SIGNAL ;
    PORT
      LAYER METAL2 ;
        RECT 6.400 28.000 9.800 31.400 ;
    END
  END B
  PIN Y
    DIRECTION INOUT ;
    USE SIGNAL ;
    PORT
      LAYER METAL2 ;
        RECT 11.800 28.000 15.200 31.400 ;
    END
  END Y
  PIN vdd
    DIRECTION INOUT ;
    USE POWER ;
    SHAPE ABUTMENT ;
    PORT
      LAYER METAL1 ;
        POLYGON 3.300 42.700 3.300 55.700 8.700 55.700 8.700 42.700 11.300 42.700 11.300 55.700 16.200 55.700 16.200 58.300 0.000 58.300 0.000 55.700 0.700 55.700 0.700 42.700 ;
    END
  END vdd
  PIN vss
    DIRECTION INOUT ;
    USE GROUND ;
    SHAPE ABUTMENT ;
    PORT
      LAYER METAL1 ;
        POLYGON 0.000 1.100 16.200 1.100 16.200 3.700 7.900 3.700 7.900 9.900 5.300 9.900 5.300 3.700 0.000 3.700 ;
    END
  END vss
  OBS
    LAYER METAL1 ;
      POLYGON 13.400 31.400 15.200 31.400 15.200 41.300 7.300 41.300 7.300 52.900 4.700 52.900 4.700 39.500 13.400 39.500 ;
      RECT 1.000 31.400 3.600 36.500 ;
      POLYGON 9.800 33.900 10.100 33.900 10.100 36.500 7.500 36.500 7.500 31.400 9.800 31.400 ;
      POLYGON 11.500 9.900 11.500 6.500 15.200 6.500 15.200 28.000 13.400 28.000 13.400 9.900 ;
  END
END NAND2

MACRO NAND3
  CLASS CORE ;
  FOREIGN NAND3 -0.000 -0.000 ;
  ORIGIN 0.000 0.000 ;
  SIZE 21.600 BY 59.400 ;
  SITE TR1UM ;
  SYMMETRY X Y ;
  PIN A
    DIRECTION INOUT ;
    USE SIGNAL ;
    PORT
      LAYER METAL2 ;
        RECT 1.000 28.000 4.400 31.400 ;
    END
  END A
  PIN B
    DIRECTION INOUT ;
    USE SIGNAL ;
    PORT
      LAYER METAL2 ;
        RECT 6.400 28.000 9.800 31.400 ;
    END
  END B
  PIN C
    DIRECTION INOUT ;
    USE SIGNAL ;
    PORT
      LAYER METAL2 ;
        RECT 11.800 28.000 15.200 31.400 ;
    END
  END C
  PIN Y
    DIRECTION INOUT ;
    USE SIGNAL ;
    PORT
      LAYER METAL2 ;
        RECT 17.200 28.000 20.600 31.400 ;
    END
  END Y
  PIN vdd
    DIRECTION INOUT ;
    USE POWER ;
    SHAPE ABUTMENT ;
    PORT
      LAYER METAL1 ;
        POLYGON 11.300 42.700 11.300 55.700 21.600 55.700 21.600 58.300 0.000 58.300 0.000 55.700 8.700 55.700 8.700 42.700 ;
    END
  END vdd
  PIN vss
    DIRECTION INOUT ;
    USE GROUND ;
    SHAPE ABUTMENT ;
    PORT
      LAYER METAL1 ;
        POLYGON 0.000 1.100 21.600 1.100 21.600 3.700 7.900 3.700 7.900 9.900 5.300 9.900 5.300 3.700 0.000 3.700 ;
    END
  END vss
  OBS
    LAYER METAL1 ;
      RECT 0.700 42.700 3.300 55.700 ;
      POLYGON 20.600 41.300 15.300 41.300 15.300 52.900 12.700 52.900 12.700 41.300 7.300 41.300 7.300 52.900 4.700 52.900 4.700 39.500 18.800 39.500 18.800 31.400 20.600 31.400 ;
      POLYGON 15.200 33.900 15.500 33.900 15.500 36.500 12.900 36.500 12.900 31.400 15.200 31.400 ;
      POLYGON 9.800 33.900 10.100 33.900 10.100 36.500 7.500 36.500 7.500 31.400 9.800 31.400 ;
      RECT 1.000 31.400 3.600 36.500 ;
      POLYGON 13.700 9.900 13.700 6.500 20.600 6.500 20.600 28.000 18.800 28.000 18.800 9.900 ;
  END
END NAND3

MACRO NAND4
  CLASS CORE ;
  FOREIGN NAND4 -0.000 -0.000 ;
  ORIGIN 0.000 0.000 ;
  SIZE 27.000 BY 59.400 ;
  SITE TR1UM ;
  SYMMETRY X Y ;
  PIN A
    DIRECTION INOUT ;
    USE SIGNAL ;
    PORT
      LAYER METAL2 ;
        RECT 1.000 28.000 4.400 31.400 ;
    END
  END A
  PIN B
    DIRECTION INOUT ;
    USE SIGNAL ;
    PORT
      LAYER METAL2 ;
        RECT 6.400 28.000 9.800 31.400 ;
    END
  END B
  PIN C
    DIRECTION INOUT ;
    USE SIGNAL ;
    PORT
      LAYER METAL2 ;
        RECT 11.800 28.000 15.200 31.400 ;
    END
  END C
  PIN D
    DIRECTION INOUT ;
    USE SIGNAL ;
    PORT
      LAYER METAL2 ;
        RECT 17.200 28.000 20.600 31.400 ;
    END
  END D
  PIN Y
    DIRECTION INOUT ;
    USE SIGNAL ;
    PORT
      LAYER METAL2 ;
        RECT 22.600 28.000 26.000 31.400 ;
    END
  END Y
  PIN vdd
    DIRECTION INOUT ;
    USE POWER ;
    SHAPE ABUTMENT ;
    PORT
      LAYER METAL1 ;
        POLYGON 19.300 42.700 19.300 55.700 27.000 55.700 27.000 58.300 0.000 58.300 0.000 55.700 16.700 55.700 16.700 42.700 ;
    END
  END vdd
  PIN vss
    DIRECTION INOUT ;
    USE GROUND ;
    SHAPE ABUTMENT ;
    PORT
      LAYER METAL1 ;
        POLYGON 0.000 1.100 27.000 1.100 27.000 3.700 7.900 3.700 7.900 9.900 5.300 9.900 5.300 3.700 0.000 3.700 ;
    END
  END vss
  OBS
    LAYER METAL1 ;
      RECT 0.700 42.700 3.300 55.700 ;
      RECT 8.700 42.700 11.300 55.700 ;
      POLYGON 26.000 41.300 15.300 41.300 15.300 52.900 12.700 52.900 12.700 41.300 7.300 41.300 7.300 52.900 4.700 52.900 4.700 39.500 24.200 39.500 24.200 31.400 26.000 31.400 ;
      POLYGON 15.200 33.900 15.500 33.900 15.500 36.500 12.900 36.500 12.900 31.400 15.200 31.400 ;
      RECT 1.000 31.400 3.600 36.500 ;
      POLYGON 9.800 33.900 10.100 33.900 10.100 36.500 7.500 36.500 7.500 31.400 9.800 31.400 ;
      POLYGON 20.600 33.900 22.100 33.900 22.100 36.500 18.300 36.500 18.300 31.400 20.600 31.400 ;
      POLYGON 15.900 9.900 15.900 6.500 26.000 6.500 26.000 28.000 24.200 28.000 24.200 9.900 ;
  END
END NAND4

MACRO NOR2
  CLASS CORE ;
  FOREIGN NOR2 -0.000 -0.000 ;
  ORIGIN 0.000 0.000 ;
  SIZE 16.200 BY 59.400 ;
  SITE TR1UM ;
  SYMMETRY X Y ;
  PIN A
    DIRECTION INOUT ;
    USE SIGNAL ;
    PORT
      LAYER METAL2 ;
        RECT 1.000 28.000 4.400 31.400 ;
    END
  END A
  PIN B
    DIRECTION INOUT ;
    USE SIGNAL ;
    PORT
      LAYER METAL2 ;
        RECT 6.400 28.000 9.800 31.400 ;
    END
  END B
  PIN Y
    DIRECTION INOUT ;
    USE SIGNAL ;
    PORT
      LAYER METAL2 ;
        RECT 11.800 28.000 15.200 31.400 ;
    END
  END Y
  PIN vdd
    DIRECTION INOUT ;
    USE POWER ;
    SHAPE ABUTMENT ;
    PORT
      LAYER METAL1 ;
        POLYGON 3.300 42.700 3.300 55.700 16.200 55.700 16.200 58.300 0.000 58.300 0.000 55.700 0.700 55.700 0.700 42.700 ;
    END
  END vdd
  PIN vss
    DIRECTION INOUT ;
    USE GROUND ;
    SHAPE ABUTMENT ;
    PORT
      LAYER METAL1 ;
        POLYGON 0.000 1.100 16.200 1.100 16.200 3.700 11.300 3.700 11.300 9.900 8.700 9.900 8.700 3.700 3.300 3.700 3.300 9.900 0.700 9.900 0.700 3.700 0.000 3.700 ;
    END
  END vss
  OBS
    LAYER METAL1 ;
      POLYGON 15.200 41.300 9.500 41.300 9.500 52.900 6.900 52.900 6.900 39.500 13.400 39.500 13.400 31.400 15.200 31.400 ;
      RECT 1.000 31.400 3.600 36.500 ;
      POLYGON 9.800 33.900 10.100 33.900 10.100 36.500 7.500 36.500 7.500 31.400 9.800 31.400 ;
      POLYGON 4.700 13.200 4.700 6.500 7.300 6.500 7.300 11.400 15.200 11.400 15.200 28.000 13.400 28.000 13.400 13.200 ;
  END
END NOR2

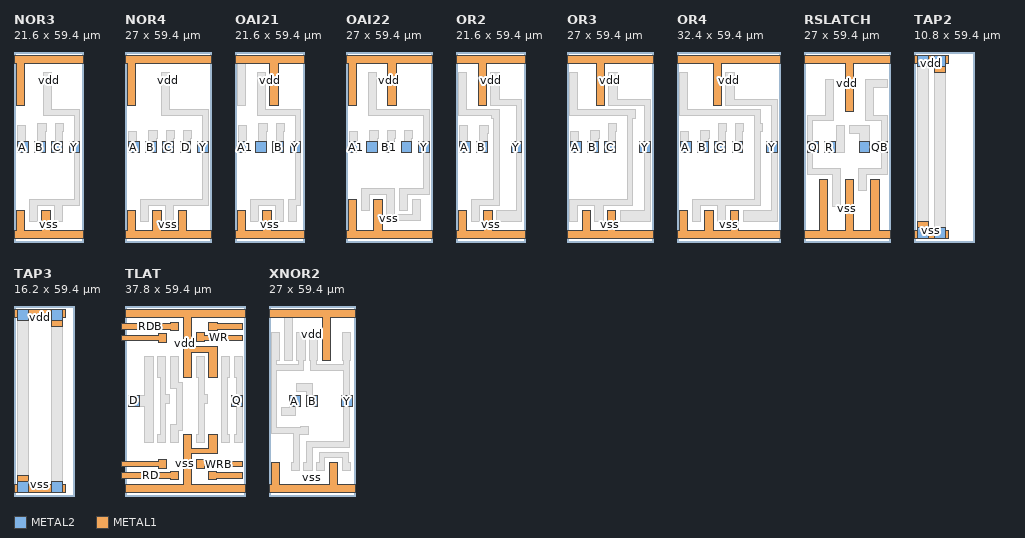
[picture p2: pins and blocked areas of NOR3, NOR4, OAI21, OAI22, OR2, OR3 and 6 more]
MACRO NOR3
  CLASS CORE ;
  FOREIGN NOR3 -0.000 -0.000 ;
  ORIGIN 0.000 0.000 ;
  SIZE 21.600 BY 59.400 ;
  SITE TR1UM ;
  SYMMETRY X Y ;
  PIN A
    DIRECTION INOUT ;
    USE SIGNAL ;
    PORT
      LAYER METAL2 ;
        RECT 1.000 28.000 4.400 31.400 ;
    END
  END A
  PIN B
    DIRECTION INOUT ;
    USE SIGNAL ;
    PORT
      LAYER METAL2 ;
        RECT 6.400 28.000 9.800 31.400 ;
    END
  END B
  PIN C
    DIRECTION INOUT ;
    USE SIGNAL ;
    PORT
      LAYER METAL2 ;
        RECT 11.800 28.000 15.200 31.400 ;
    END
  END C
  PIN Y
    DIRECTION INOUT ;
    USE SIGNAL ;
    PORT
      LAYER METAL2 ;
        RECT 17.200 28.000 20.600 31.400 ;
    END
  END Y
  PIN vdd
    DIRECTION INOUT ;
    USE POWER ;
    SHAPE ABUTMENT ;
    PORT
      LAYER METAL1 ;
        POLYGON 3.300 42.700 3.300 55.700 21.600 55.700 21.600 58.300 0.000 58.300 0.000 55.700 0.700 55.700 0.700 42.700 ;
    END
  END vdd
  PIN vss
    DIRECTION INOUT ;
    USE GROUND ;
    SHAPE ABUTMENT ;
    PORT
      LAYER METAL1 ;
        POLYGON 0.000 1.100 21.600 1.100 21.600 3.700 11.300 3.700 11.300 9.900 8.700 9.900 8.700 3.700 3.300 3.700 3.300 9.900 0.700 9.900 0.700 3.700 0.000 3.700 ;
    END
  END vss
  OBS
    LAYER METAL1 ;
      POLYGON 20.600 41.300 11.700 41.300 11.700 52.900 9.100 52.900 9.100 39.500 18.800 39.500 18.800 31.400 20.600 31.400 ;
      POLYGON 9.800 34.500 10.100 34.500 10.100 37.100 7.500 37.100 7.500 31.400 9.800 31.400 ;
      POLYGON 15.200 34.400 15.500 34.400 15.500 37.000 12.900 37.000 12.900 31.400 15.200 31.400 ;
      RECT 1.000 31.400 3.600 36.500 ;
      POLYGON 4.700 13.200 4.700 6.500 7.300 6.500 7.300 11.400 12.700 11.400 12.700 6.500 15.300 6.500 15.300 11.400 20.600 11.400 20.600 28.000 18.800 28.000 18.800 13.200 ;
  END
END NOR3

MACRO NOR4
  CLASS CORE ;
  FOREIGN NOR4 -0.000 -0.000 ;
  ORIGIN 0.000 0.000 ;
  SIZE 27.000 BY 59.400 ;
  SITE TR1UM ;
  SYMMETRY X Y ;
  PIN A
    DIRECTION INOUT ;
    USE SIGNAL ;
    PORT
      LAYER METAL2 ;
        RECT 1.000 28.000 4.400 31.400 ;
    END
  END A
  PIN B
    DIRECTION INOUT ;
    USE SIGNAL ;
    PORT
      LAYER METAL2 ;
        RECT 6.400 28.000 9.800 31.400 ;
    END
  END B
  PIN C
    DIRECTION INOUT ;
    USE SIGNAL ;
    PORT
      LAYER METAL2 ;
        RECT 11.800 28.000 15.200 31.400 ;
    END
  END C
  PIN D
    DIRECTION INOUT ;
    USE SIGNAL ;
    PORT
      LAYER METAL2 ;
        RECT 17.200 28.000 20.600 31.400 ;
    END
  END D
  PIN Y
    DIRECTION INOUT ;
    USE SIGNAL ;
    PORT
      LAYER METAL2 ;
        RECT 22.600 28.000 26.000 31.400 ;
    END
  END Y
  PIN vdd
    DIRECTION INOUT ;
    USE POWER ;
    SHAPE ABUTMENT ;
    PORT
      LAYER METAL1 ;
        POLYGON 3.300 42.700 3.300 55.700 27.000 55.700 27.000 58.300 0.000 58.300 0.000 55.700 0.700 55.700 0.700 42.700 ;
    END
  END vdd
  PIN vss
    DIRECTION INOUT ;
    USE GROUND ;
    SHAPE ABUTMENT ;
    PORT
      LAYER METAL1 ;
        POLYGON 0.000 1.100 27.000 1.100 27.000 3.700 19.300 3.700 19.300 9.900 16.700 9.900 16.700 3.700 11.300 3.700 11.300 9.900 8.700 9.900 8.700 3.700 3.300 3.700 3.300 9.900 0.700 9.900 0.700 3.700 0.000 3.700 ;
    END
  END vss
  OBS
    LAYER METAL1 ;
      POLYGON 26.000 41.300 13.900 41.300 13.900 52.900 11.300 52.900 11.300 39.500 24.200 39.500 24.200 31.400 26.000 31.400 ;
      POLYGON 15.200 32.400 15.500 32.400 15.500 35.000 12.900 35.000 12.900 31.400 15.200 31.400 ;
      POLYGON 9.800 32.400 10.100 32.400 10.100 35.000 7.500 35.000 7.500 31.400 9.800 31.400 ;
      POLYGON 20.600 32.400 20.900 32.400 20.900 35.000 18.300 35.000 18.300 31.400 20.600 31.400 ;
      RECT 1.000 31.400 3.600 34.400 ;
      POLYGON 4.700 13.200 4.700 6.500 7.300 6.500 7.300 11.400 12.700 11.400 12.700 6.500 15.300 6.500 15.300 11.400 26.000 11.400 26.000 28.000 24.200 28.000 24.200 13.200 ;
  END
END NOR4

MACRO OAI21
  CLASS CORE ;
  FOREIGN OAI21 -0.000 -0.000 ;
  ORIGIN 0.000 0.000 ;
  SIZE 21.600 BY 59.400 ;
  SITE TR1UM ;
  SYMMETRY X Y ;
  PIN A1
    DIRECTION INOUT ;
    USE SIGNAL ;
    PORT
      LAYER METAL2 ;
        RECT 1.000 28.000 4.400 31.400 ;
    END
  END A1
  PIN A2
    DIRECTION INOUT ;
    USE SIGNAL ;
    PORT
      LAYER METAL2 ;
        RECT 6.400 28.000 9.800 31.400 ;
    END
  END A2
  PIN B
    DIRECTION INOUT ;
    USE SIGNAL ;
    PORT
      LAYER METAL2 ;
        RECT 11.800 28.000 15.200 31.400 ;
    END
  END B
  PIN Y
    DIRECTION INOUT ;
    USE SIGNAL ;
    PORT
      LAYER METAL2 ;
        RECT 17.200 28.000 20.600 31.400 ;
    END
  END Y
  PIN vdd
    DIRECTION INOUT ;
    USE POWER ;
    SHAPE ABUTMENT ;
    PORT
      LAYER METAL1 ;
        POLYGON 13.500 42.700 13.500 55.700 21.600 55.700 21.600 58.300 0.000 58.300 0.000 55.700 10.900 55.700 10.900 42.700 ;
    END
  END vdd
  PIN vss
    DIRECTION INOUT ;
    USE GROUND ;
    SHAPE ABUTMENT ;
    PORT
      LAYER METAL1 ;
        POLYGON 0.000 1.100 21.600 1.100 21.600 3.700 11.300 3.700 11.300 9.900 8.700 9.900 8.700 3.700 3.300 3.700 3.300 9.900 0.700 9.900 0.700 3.700 0.000 3.700 ;
    END
  END vss
  OBS
    LAYER METAL1 ;
      RECT 0.700 42.700 3.300 55.700 ;
      POLYGON 20.600 41.300 9.500 41.300 9.500 52.900 6.900 52.900 6.900 39.500 18.800 39.500 18.800 31.400 20.600 31.400 ;
      POLYGON 9.800 34.500 10.100 34.500 10.100 37.100 7.500 37.100 7.500 31.400 9.800 31.400 ;
      POLYGON 15.200 34.400 15.500 34.400 15.500 37.000 12.900 37.000 12.900 31.400 15.200 31.400 ;
      RECT 1.000 31.400 3.600 36.500 ;
      POLYGON 7.300 11.400 12.700 11.400 12.700 6.500 15.300 6.500 15.300 13.200 4.700 13.200 4.700 6.500 7.300 6.500 ;
      POLYGON 16.700 13.200 16.700 6.500 19.300 6.500 19.300 11.400 20.600 11.400 20.600 28.000 18.800 28.000 18.800 13.200 ;
  END
END OAI21

MACRO OAI22
  CLASS CORE ;
  FOREIGN OAI22 -0.000 -0.000 ;
  ORIGIN 0.000 0.000 ;
  SIZE 27.000 BY 59.400 ;
  SITE TR1UM ;
  SYMMETRY X Y ;
  PIN A1
    DIRECTION INOUT ;
    USE SIGNAL ;
    PORT
      LAYER METAL2 ;
        RECT 1.000 28.000 4.400 31.400 ;
    END
  END A1
  PIN A2
    DIRECTION INOUT ;
    USE SIGNAL ;
    PORT
      LAYER METAL2 ;
        RECT 6.400 28.000 9.800 31.400 ;
    END
  END A2
  PIN B1
    DIRECTION INOUT ;
    USE SIGNAL ;
    PORT
      LAYER METAL2 ;
        RECT 11.800 28.000 15.200 31.400 ;
    END
  END B1
  PIN B2
    DIRECTION INOUT ;
    USE SIGNAL ;
    PORT
      LAYER METAL2 ;
        RECT 17.200 28.000 20.600 31.400 ;
    END
  END B2
  PIN Y
    DIRECTION INOUT ;
    USE SIGNAL ;
    PORT
      LAYER METAL2 ;
        RECT 22.600 28.000 26.000 31.400 ;
    END
  END Y
  PIN vdd
    DIRECTION INOUT ;
    USE POWER ;
    SHAPE ABUTMENT ;
    PORT
      LAYER METAL1 ;
        POLYGON 3.300 42.700 3.300 55.700 13.100 55.700 13.100 42.700 15.700 42.700 15.700 55.700 27.000 55.700 27.000 58.300 0.000 58.300 0.000 55.700 0.700 55.700 0.700 42.700 ;
    END
  END vdd
  PIN vss
    DIRECTION INOUT ;
    USE GROUND ;
    SHAPE ABUTMENT ;
    PORT
      LAYER METAL1 ;
        POLYGON 0.000 1.100 27.000 1.100 27.000 3.700 11.300 3.700 11.300 13.400 8.700 13.400 8.700 3.700 3.300 3.700 3.300 13.400 0.700 13.400 0.700 3.700 0.000 3.700 ;
    END
  END vss
  OBS
    LAYER METAL1 ;
      POLYGON 26.000 41.300 9.500 41.300 9.500 52.900 6.900 52.900 6.900 39.500 24.200 39.500 24.200 31.400 26.000 31.400 ;
      POLYGON 20.600 32.400 20.900 32.400 20.900 35.000 18.300 35.000 18.300 31.400 20.600 31.400 ;
      POLYGON 15.200 32.400 15.500 32.400 15.500 35.000 12.900 35.000 12.900 31.400 15.200 31.400 ;
      POLYGON 9.800 32.400 10.100 32.400 10.100 35.000 7.500 35.000 7.500 31.400 9.800 31.400 ;
      RECT 1.000 31.400 3.600 34.400 ;
      POLYGON 23.300 13.400 20.700 13.400 20.700 8.600 15.300 8.600 15.300 16.700 4.700 16.700 4.700 10.000 7.300 10.000 7.300 14.900 12.700 14.900 12.700 6.800 23.300 6.800 ;
      POLYGON 16.700 16.700 16.700 10.000 19.300 10.000 19.300 14.900 26.000 14.900 26.000 28.000 24.200 28.000 24.200 16.700 ;
  END
END OAI22

MACRO OR2
  CLASS CORE ;
  FOREIGN OR2 -0.000 -0.000 ;
  ORIGIN 0.000 0.000 ;
  SIZE 21.600 BY 59.400 ;
  SITE TR1UM ;
  SYMMETRY X Y ;
  PIN A
    DIRECTION INOUT ;
    USE SIGNAL ;
    PORT
      LAYER METAL2 ;
        RECT 1.000 28.000 4.400 31.400 ;
    END
  END A
  PIN B
    DIRECTION INOUT ;
    USE SIGNAL ;
    PORT
      LAYER METAL2 ;
        RECT 6.400 28.000 9.800 31.400 ;
    END
  END B
  PIN Y
    DIRECTION INOUT ;
    USE SIGNAL ;
    PORT
      LAYER METAL2 ;
        RECT 17.200 28.000 20.600 31.400 ;
        RECT 17.200 28.000 20.600 31.400 ;
    END
  END Y
  PIN vdd
    DIRECTION INOUT ;
    USE POWER ;
    SHAPE ABUTMENT ;
    PORT
      LAYER METAL1 ;
        POLYGON 9.500 42.700 9.500 55.700 21.600 55.700 21.600 58.300 0.000 58.300 0.000 55.700 6.900 55.700 6.900 42.700 ;
    END
  END vdd
  PIN vss
    DIRECTION INOUT ;
    USE GROUND ;
    SHAPE ABUTMENT ;
    PORT
      LAYER METAL1 ;
        POLYGON 0.000 1.100 21.600 1.100 21.600 3.700 11.300 3.700 11.300 9.900 8.700 9.900 8.700 3.700 3.300 3.700 3.300 9.900 0.700 9.900 0.700 3.700 0.000 3.700 ;
    END
  END vss
  OBS
    LAYER METAL1 ;
      POLYGON 7.300 11.400 13.600 11.400 13.600 41.300 3.300 41.300 3.300 52.900 0.700 52.900 0.700 39.500 11.000 39.500 11.000 38.700 11.800 38.700 11.800 13.200 4.700 13.200 4.700 6.500 7.300 6.500 ;
      POLYGON 10.900 52.900 10.900 42.700 18.800 42.700 18.800 31.400 20.600 31.400 20.600 44.500 13.500 44.500 13.500 52.900 ;
      RECT 1.000 31.400 3.600 36.500 ;
      POLYGON 9.800 33.900 10.100 33.900 10.100 36.500 7.500 36.500 7.500 31.400 9.800 31.400 ;
      POLYGON 20.600 28.000 18.800 28.000 18.800 9.900 12.700 9.900 12.700 6.500 20.600 6.500 ;
  END
END OR2

MACRO OR3
  CLASS CORE ;
  FOREIGN OR3 -0.000 -0.000 ;
  ORIGIN 0.000 0.000 ;
  SIZE 27.000 BY 59.400 ;
  SITE TR1UM ;
  SYMMETRY X Y ;
  PIN A
    DIRECTION INOUT ;
    USE SIGNAL ;
    PORT
      LAYER METAL2 ;
        RECT 1.000 28.000 4.400 31.400 ;
    END
  END A
  PIN B
    DIRECTION INOUT ;
    USE SIGNAL ;
    PORT
      LAYER METAL2 ;
        RECT 6.400 28.000 9.800 31.400 ;
    END
  END B
  PIN C
    DIRECTION INOUT ;
    USE SIGNAL ;
    PORT
      LAYER METAL2 ;
        RECT 11.800 28.000 15.200 31.400 ;
    END
  END C
  PIN Y
    DIRECTION INOUT ;
    USE SIGNAL ;
    PORT
      LAYER METAL2 ;
        RECT 22.600 28.000 26.000 31.400 ;
    END
  END Y
  PIN vdd
    DIRECTION INOUT ;
    USE POWER ;
    SHAPE ABUTMENT ;
    PORT
      LAYER METAL1 ;
        POLYGON 11.700 42.700 11.700 55.700 27.000 55.700 27.000 58.300 0.000 58.300 0.000 55.700 9.100 55.700 9.100 42.700 ;
    END
  END vdd
  PIN vss
    DIRECTION INOUT ;
    USE GROUND ;
    SHAPE ABUTMENT ;
    PORT
      LAYER METAL1 ;
        POLYGON 0.000 1.100 27.000 1.100 27.000 3.700 15.300 3.700 15.300 9.900 12.700 9.900 12.700 3.700 7.300 3.700 7.300 9.900 4.700 9.900 4.700 3.700 0.000 3.700 ;
    END
  END vss
  OBS
    LAYER METAL1 ;
      POLYGON 21.400 38.600 21.400 41.300 3.300 41.300 3.300 52.900 0.700 52.900 0.700 39.500 18.800 39.500 18.800 13.200 0.700 13.200 0.700 6.500 3.300 6.500 3.300 11.400 8.700 11.400 8.700 6.500 11.300 6.500 11.300 11.400 20.600 11.400 20.600 38.600 ;
      POLYGON 26.000 44.500 15.700 44.500 15.700 52.900 13.100 52.900 13.100 42.700 24.200 42.700 24.200 31.400 26.000 31.400 ;
      POLYGON 15.200 34.600 15.500 34.600 15.500 37.200 12.900 37.200 12.900 31.400 15.200 31.400 ;
      POLYGON 9.800 32.400 10.100 32.400 10.100 35.000 7.500 35.000 7.500 31.400 9.800 31.400 ;
      RECT 1.000 31.400 3.600 34.400 ;
      POLYGON 16.700 9.900 16.700 6.500 26.000 6.500 26.000 28.000 24.200 28.000 24.200 9.900 ;
  END
END OR3

MACRO OR4
  CLASS CORE ;
  FOREIGN OR4 -0.000 -0.000 ;
  ORIGIN 0.000 0.000 ;
  SIZE 32.400 BY 59.400 ;
  SITE TR1UM ;
  SYMMETRY X Y ;
  PIN A
    DIRECTION INOUT ;
    USE SIGNAL ;
    PORT
      LAYER METAL2 ;
        RECT 1.000 28.000 4.400 31.400 ;
    END
  END A
  PIN B
    DIRECTION INOUT ;
    USE SIGNAL ;
    PORT
      LAYER METAL2 ;
        RECT 6.400 28.000 9.800 31.400 ;
    END
  END B
  PIN C
    DIRECTION INOUT ;
    USE SIGNAL ;
    PORT
      LAYER METAL2 ;
        RECT 11.800 28.000 15.200 31.400 ;
    END
  END C
  PIN D
    DIRECTION INOUT ;
    USE SIGNAL ;
    PORT
      LAYER METAL2 ;
        RECT 17.200 28.000 20.600 31.400 ;
    END
  END D
  PIN Y
    DIRECTION INOUT ;
    USE SIGNAL ;
    PORT
      LAYER METAL2 ;
        RECT 28.000 28.000 31.400 31.400 ;
    END
  END Y
  PIN vdd
    DIRECTION INOUT ;
    USE POWER ;
    SHAPE ABUTMENT ;
    PORT
      LAYER METAL1 ;
        POLYGON 13.900 42.700 13.900 55.700 32.400 55.700 32.400 58.300 0.000 58.300 0.000 55.700 11.300 55.700 11.300 42.700 ;
    END
  END vdd
  PIN vss
    DIRECTION INOUT ;
    USE GROUND ;
    SHAPE ABUTMENT ;
    PORT
      LAYER METAL1 ;
        POLYGON 0.000 1.100 32.400 1.100 32.400 3.700 19.300 3.700 19.300 9.900 16.700 9.900 16.700 3.700 11.300 3.700 11.300 9.900 8.700 9.900 8.700 3.700 3.300 3.700 3.300 9.900 0.700 9.900 0.700 3.700 0.000 3.700 ;
    END
  END vss
  OBS
    LAYER METAL1 ;
      POLYGON 31.400 44.500 17.900 44.500 17.900 52.900 15.300 52.900 15.300 42.700 29.600 42.700 29.600 31.400 31.400 31.400 ;
      POLYGON 7.300 11.400 12.700 11.400 12.700 6.500 15.300 6.500 15.300 11.400 26.000 11.400 26.000 34.600 26.800 34.600 26.800 37.200 26.000 37.200 26.000 41.300 3.300 41.300 3.300 52.900 0.700 52.900 0.700 39.500 24.200 39.500 24.200 13.200 4.700 13.200 4.700 6.500 7.300 6.500 ;
      POLYGON 15.200 34.600 15.500 34.600 15.500 37.200 12.900 37.200 12.900 31.400 15.200 31.400 ;
      POLYGON 20.600 34.600 20.900 34.600 20.900 37.200 18.300 37.200 18.300 31.400 20.600 31.400 ;
      POLYGON 9.800 32.400 10.100 32.400 10.100 35.000 7.500 35.000 7.500 31.400 9.800 31.400 ;
      RECT 1.000 31.400 3.600 34.400 ;
      POLYGON 20.700 9.900 20.700 6.500 31.400 6.500 31.400 28.000 29.600 28.000 29.600 9.900 ;
  END
END OR4

MACRO RSLATCH
  CLASS CORE ;
  FOREIGN RSLATCH -0.000 -0.000 ;
  ORIGIN 0.000 0.000 ;
  SIZE 27.000 BY 59.400 ;
  SITE TR1UM ;
  SYMMETRY X Y ;
  PIN Q
    DIRECTION INOUT ;
    USE SIGNAL ;
    PORT
      LAYER METAL2 ;
        RECT 1.000 28.000 4.400 31.400 ;
    END
  END Q
  PIN QB
    DIRECTION INOUT ;
    USE SIGNAL ;
    PORT
      LAYER METAL2 ;
        RECT 22.600 28.000 26.000 31.400 ;
    END
  END QB
  PIN R
    DIRECTION INOUT ;
    USE SIGNAL ;
    PORT
      LAYER METAL2 ;
        RECT 6.400 28.000 9.800 31.400 ;
    END
  END R
  PIN S
    DIRECTION INOUT ;
    USE SIGNAL ;
    PORT
      LAYER METAL2 ;
        RECT 17.200 28.000 20.600 31.400 ;
    END
  END S
  PIN vdd
    DIRECTION INOUT ;
    USE POWER ;
    SHAPE ABUTMENT ;
    PORT
      LAYER METAL1 ;
        POLYGON 15.500 40.700 15.500 55.700 27.000 55.700 27.000 58.300 0.000 58.300 0.000 55.700 12.900 55.700 12.900 40.700 ;
    END
  END vdd
  PIN vss
    DIRECTION INOUT ;
    USE GROUND ;
    SHAPE ABUTMENT ;
    PORT
      LAYER METAL1 ;
        POLYGON 0.000 1.100 27.000 1.100 27.000 3.700 23.500 3.700 23.500 19.600 20.900 19.600 20.900 3.700 15.500 3.700 15.500 19.600 12.900 19.600 12.900 3.700 7.500 3.700 7.500 19.600 4.900 19.600 4.900 3.700 0.000 3.700 ;
    END
  END vss
  OBS
    LAYER METAL1 ;
      POLYGON 26.000 39.700 21.700 39.700 21.700 48.300 26.000 48.300 26.000 50.900 19.100 50.900 19.100 37.900 24.200 37.900 24.200 31.400 26.000 31.400 ;
      POLYGON 2.800 37.900 9.300 37.900 9.300 50.900 6.700 50.900 6.700 39.700 1.000 39.700 1.000 31.400 2.800 31.400 ;
      POLYGON 20.600 36.500 14.100 36.500 14.100 33.900 17.200 33.900 17.200 31.400 20.600 31.400 ;
      POLYGON 9.800 28.000 12.700 28.000 12.700 36.500 10.100 36.500 10.100 31.400 9.800 31.400 ;
      POLYGON 16.900 22.900 16.900 16.200 19.500 16.200 19.500 21.100 26.000 21.100 26.000 28.000 24.200 28.000 24.200 22.900 ;
      POLYGON 8.900 21.100 8.900 11.000 11.500 11.000 11.500 22.900 2.800 22.900 2.800 28.000 1.000 28.000 1.000 21.100 ;
  END
END RSLATCH

MACRO TAP2
  CLASS CORE WELLTAP ;
  FOREIGN TAP2 -0.000 -0.000 ;
  ORIGIN 0.000 0.000 ;
  SIZE 10.800 BY 59.400 ;
  SITE TR1UM ;
  SYMMETRY X Y ;
  PIN vdd
    DIRECTION INOUT ;
    USE POWER ;
    SHAPE ABUTMENT ;
    PORT
      LAYER METAL2 ;
        RECT 6.400 54.900 9.800 58.300 ;
        RECT 6.400 1.100 9.800 4.500 ;
      LAYER METAL1 ;
        POLYGON 9.800 55.700 10.800 55.700 10.800 58.300 0.000 58.300 0.000 55.700 6.400 55.700 6.400 53.100 9.800 53.100 ;
    END
  END vdd
  PIN vss
    DIRECTION INOUT ;
    USE GROUND ;
    SHAPE ABUTMENT ;
    PORT
      LAYER METAL2 ;
        RECT 1.000 54.900 4.400 58.300 ;
        RECT 1.000 1.100 4.400 4.500 ;
      LAYER METAL1 ;
        POLYGON 10.800 3.700 4.400 3.700 4.400 6.300 1.000 6.300 1.000 3.700 0.000 3.700 0.000 1.100 10.800 1.100 ;
    END
  END vss
  OBS
    LAYER METAL2 ;
      RECT 6.400 4.500 9.800 53.100 ;
      RECT 1.000 6.300 4.400 54.900 ;
  END
END TAP2

MACRO TAP3
  CLASS CORE WELLTAP ;
  FOREIGN TAP3 -0.000 -0.000 ;
  ORIGIN 0.000 0.000 ;
  SIZE 16.200 BY 59.400 ;
  SITE TR1UM ;
  SYMMETRY X Y ;
  PIN vdd
    DIRECTION INOUT ;
    USE POWER ;
    SHAPE ABUTMENT ;
    PORT
      LAYER METAL2 ;
        RECT 11.800 54.900 15.200 58.300 ;
        RECT 11.800 1.100 15.200 4.500 ;
      LAYER METAL1 ;
        POLYGON 15.200 55.700 16.200 55.700 16.200 58.300 0.000 58.300 0.000 55.700 11.800 55.700 11.800 53.100 15.200 53.100 ;
    END
  END vdd
  PIN vss
    DIRECTION INOUT ;
    USE GROUND ;
    SHAPE ABUTMENT ;
    PORT
      LAYER METAL2 ;
        RECT 1.000 54.900 4.400 58.300 ;
        RECT 1.000 1.100 4.400 4.500 ;
      LAYER METAL1 ;
        POLYGON 16.200 3.700 4.400 3.700 4.400 6.300 1.000 6.300 1.000 3.700 0.000 3.700 0.000 1.100 16.200 1.100 ;
    END
  END vss
  OBS
    LAYER METAL2 ;
      RECT 11.800 4.500 15.200 53.100 ;
      RECT 1.000 6.300 4.400 54.900 ;
  END
END TAP3

MACRO TLAT
  CLASS BLOCK ;
  FOREIGN TLAT -0.000 -0.000 ;
  ORIGIN 0.000 0.000 ;
  SIZE 37.800 BY 59.400 ;
  SYMMETRY X Y ;
  PIN D
    DIRECTION INOUT ;
    USE SIGNAL ;
    PORT
      LAYER METAL2 ;
        RECT 1.000 28.100 4.400 31.500 ;
    END
  END D
  PIN Q
    DIRECTION INOUT ;
    USE SIGNAL ;
    PORT
      LAYER METAL2 ;
        RECT 33.400 28.100 36.800 31.500 ;
    END
  END Q
  PIN RD
    DIRECTION INOUT ;
    USE SIGNAL ;
    PORT
      LAYER METAL1 ;
        POLYGON 28.600 5.500 36.800 5.500 36.800 7.300 28.600 7.300 28.600 7.700 26.000 7.700 26.000 5.100 28.600 5.100 ;
        POLYGON 16.800 7.700 14.200 7.700 14.200 7.300 -1.000 7.300 -1.000 5.500 14.200 5.500 14.200 5.100 16.800 5.100 ;
    END
  END RD
  PIN RDB
    DIRECTION INOUT ;
    USE SIGNAL ;
    PORT
      LAYER METAL1 ;
        POLYGON 28.800 52.100 36.800 52.100 36.800 53.900 28.800 53.900 28.800 54.300 26.200 54.300 26.200 51.700 28.800 51.700 ;
        POLYGON 16.800 54.300 14.200 54.300 14.200 53.900 -1.000 53.900 -1.000 52.100 14.200 52.100 14.200 51.700 16.800 51.700 ;
    END
  END RDB
  PIN WR
    DIRECTION INOUT ;
    USE SIGNAL ;
    PORT
      LAYER METAL1 ;
        POLYGON 24.800 48.500 36.800 48.500 36.800 50.300 24.800 50.300 24.800 51.000 22.200 51.000 22.200 48.400 24.800 48.400 ;
        POLYGON 13.000 50.700 10.400 50.700 10.400 50.300 -1.000 50.300 -1.000 48.500 10.400 48.500 10.400 48.100 13.000 48.100 ;
    END
  END WR
  PIN WRB
    DIRECTION INOUT ;
    USE SIGNAL ;
    PORT
      LAYER METAL1 ;
        POLYGON 24.800 9.100 36.800 9.100 36.800 10.900 24.800 10.900 24.800 11.300 22.200 11.300 22.200 8.700 24.800 8.700 ;
        POLYGON 13.000 11.300 10.400 11.300 10.400 10.900 -1.000 10.900 -1.000 9.100 10.400 9.100 10.400 8.700 13.000 8.700 ;
    END
  END WRB
  PIN vdd
    DIRECTION INOUT ;
    USE POWER ;
    SHAPE ABUTMENT ;
    PORT
      LAYER METAL1 ;
        POLYGON 20.800 36.900 20.800 44.900 26.200 44.900 26.200 36.900 28.800 36.900 28.800 46.700 20.800 46.700 20.800 55.700 37.800 55.700 37.800 58.300 0.000 58.300 0.000 55.700 18.200 55.700 18.200 36.900 ;
    END
  END vdd
  PIN vss
    DIRECTION INOUT ;
    USE GROUND ;
    SHAPE ABUTMENT ;
    PORT
      LAYER METAL1 ;
        POLYGON 0.000 1.100 37.800 1.100 37.800 3.700 20.800 3.700 20.800 13.200 28.800 13.200 28.800 19.200 26.200 19.200 26.200 15.000 20.800 15.000 20.800 19.200 18.200 19.200 18.200 3.700 0.000 3.700 ;
    END
  END vss
  OBS
    LAYER METAL1 ;
      POLYGON 32.800 19.200 32.000 19.200 32.000 36.900 32.800 36.900 32.800 43.500 30.200 43.500 30.200 16.600 32.800 16.600 ;
      POLYGON 12.800 29.000 13.800 29.000 13.800 31.600 12.800 31.600 12.800 43.500 10.200 43.500 10.200 36.900 11.000 36.900 11.000 19.200 10.200 19.200 10.200 16.600 12.800 16.600 ;
      POLYGON 16.800 20.600 18.000 20.600 18.000 35.500 16.800 35.500 16.800 43.500 14.200 43.500 14.200 33.700 16.200 33.700 16.200 22.400 14.200 22.400 14.200 16.600 16.800 16.600 ;
      POLYGON 36.800 43.500 34.200 43.500 34.200 36.900 35.000 36.900 35.000 31.500 36.800 31.500 ;
      POLYGON 24.800 29.000 25.800 29.000 25.800 31.600 24.800 31.600 24.800 43.500 22.200 43.500 22.200 36.900 23.000 36.900 23.000 19.300 22.200 19.300 22.200 16.600 24.800 16.600 ;
      POLYGON 6.200 28.100 6.200 16.600 8.800 16.600 8.800 43.500 6.200 43.500 6.200 31.500 4.400 31.500 4.400 28.100 ;
      POLYGON 36.800 28.100 35.000 28.100 35.000 19.200 34.200 19.200 34.200 16.600 36.800 16.600 ;
  END
END TLAT

MACRO XNOR2
  CLASS CORE ;
  FOREIGN XNOR2 -0.000 -0.000 ;
  ORIGIN 0.000 0.000 ;
  SIZE 27.000 BY 59.400 ;
  SITE TR1UM ;
  SYMMETRY X Y ;
  PIN A
    DIRECTION INOUT ;
    USE SIGNAL ;
    PORT
      LAYER METAL2 ;
        RECT 6.400 27.900 9.800 31.300 ;
    END
  END A
  PIN B
    DIRECTION INOUT ;
    USE SIGNAL ;
    PORT
      LAYER METAL2 ;
        RECT 11.800 27.900 15.200 31.300 ;
    END
  END B
  PIN Y
    DIRECTION INOUT ;
    USE SIGNAL ;
    PORT
      LAYER METAL2 ;
        RECT 22.600 27.900 26.000 31.300 ;
    END
  END Y
  PIN vdd
    DIRECTION INOUT ;
    USE POWER ;
    SHAPE ABUTMENT ;
    PORT
      LAYER METAL1 ;
        POLYGON 19.300 42.500 19.300 55.700 27.000 55.700 27.000 58.300 0.000 58.300 0.000 55.700 16.700 55.700 16.700 42.500 ;
    END
  END vdd
  PIN vss
    DIRECTION INOUT ;
    USE GROUND ;
    SHAPE ABUTMENT ;
    PORT
      LAYER METAL1 ;
        POLYGON 0.000 1.100 27.000 1.100 27.000 3.700 21.500 3.700 21.500 10.500 18.900 10.500 18.900 3.700 3.300 3.700 3.300 10.500 0.700 10.500 0.700 3.700 0.000 3.700 ;
    END
  END vss
  OBS
    LAYER METAL1 ;
      RECT 4.700 42.500 7.300 55.700 ;
      POLYGON 25.100 42.500 25.500 42.500 25.500 51.100 22.900 51.100 22.900 42.500 23.300 42.500 23.300 41.100 14.900 41.100 14.900 42.500 15.300 42.500 15.300 51.100 12.700 51.100 12.700 42.500 13.100 42.500 13.100 39.300 23.300 39.300 23.300 31.300 25.100 31.300 ;
      POLYGON 9.500 19.100 12.300 19.100 12.300 21.700 9.700 21.700 9.700 21.400 2.500 21.400 2.500 39.300 10.900 39.300 10.900 42.500 11.300 42.500 11.300 51.100 8.700 51.100 8.700 42.500 9.100 42.500 9.100 41.100 2.500 41.100 2.500 42.500 3.300 42.500 3.300 51.100 0.700 51.100 0.700 19.600 7.700 19.600 7.700 10.500 6.900 10.500 6.900 7.900 9.500 7.900 ;
      POLYGON 13.600 35.300 8.700 35.300 8.700 32.700 11.800 32.700 11.800 31.300 13.600 31.300 ;
      POLYGON 3.900 27.700 3.900 25.100 8.200 25.100 8.200 27.900 6.400 27.900 6.400 27.700 ;
      POLYGON 17.500 11.900 22.900 11.900 22.900 7.900 25.500 7.900 25.500 10.500 24.700 10.500 24.700 13.700 15.700 13.700 15.700 10.500 14.900 10.500 14.900 7.900 17.500 7.900 ;
      POLYGON 11.700 16.900 11.700 10.500 10.900 10.500 10.900 7.900 13.500 7.900 13.500 15.100 25.100 15.100 25.100 27.900 23.300 27.900 23.300 16.900 ;
  END
END XNOR2

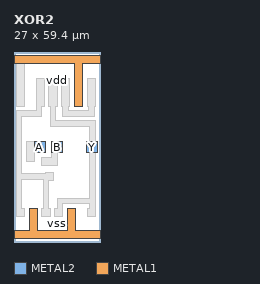
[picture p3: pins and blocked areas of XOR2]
MACRO XOR2
  CLASS CORE ;
  FOREIGN XOR2 -0.000 -0.000 ;
  ORIGIN 0.000 0.000 ;
  SIZE 27.000 BY 59.400 ;
  SITE TR1UM ;
  SYMMETRY X Y ;
  PIN A
    DIRECTION INOUT ;
    USE SIGNAL ;
    PORT
      LAYER METAL2 ;
        RECT 6.400 27.900 9.800 31.300 ;
    END
  END A
  PIN B
    DIRECTION INOUT ;
    USE SIGNAL ;
    PORT
      LAYER METAL2 ;
        RECT 11.800 27.900 15.200 31.300 ;
    END
  END B
  PIN Y
    DIRECTION INOUT ;
    USE SIGNAL ;
    PORT
      LAYER METAL2 ;
        RECT 22.600 27.900 26.000 31.300 ;
    END
  END Y
  PIN vdd
    DIRECTION INOUT ;
    USE POWER ;
    SHAPE ABUTMENT ;
    PORT
      LAYER METAL1 ;
        POLYGON 21.500 42.500 21.500 55.700 27.000 55.700 27.000 58.300 0.000 58.300 0.000 55.700 18.900 55.700 18.900 42.500 ;
    END
  END vdd
  PIN vss
    DIRECTION INOUT ;
    USE GROUND ;
    SHAPE ABUTMENT ;
    PORT
      LAYER METAL1 ;
        POLYGON 0.000 1.100 27.000 1.100 27.000 3.700 19.300 3.700 19.300 10.500 16.700 10.500 16.700 3.700 7.300 3.700 7.300 10.500 4.700 10.500 4.700 3.700 0.000 3.700 ;
    END
  END vss
  OBS
    LAYER METAL1 ;
      RECT 0.700 42.500 3.300 55.700 ;
      POLYGON 25.100 42.500 25.500 42.500 25.500 51.100 22.900 51.100 22.900 42.500 23.300 42.500 23.300 41.100 17.100 41.100 17.100 42.500 17.500 42.500 17.500 51.100 14.900 51.100 14.900 42.500 15.300 42.500 15.300 39.300 25.100 39.300 ;
      POLYGON 25.400 37.900 13.100 37.900 13.100 42.500 13.500 42.500 13.500 51.100 10.900 51.100 10.900 42.500 11.300 42.500 11.300 36.100 23.600 36.100 23.600 31.300 25.400 31.300 ;
      POLYGON 3.300 10.500 2.500 10.500 2.500 19.600 9.100 19.600 9.100 10.500 8.700 10.500 8.700 7.900 11.300 7.900 11.300 10.500 10.900 10.500 10.900 19.100 12.300 19.100 12.300 21.700 9.700 21.700 9.700 21.400 2.500 21.400 2.500 39.300 8.700 39.300 8.700 42.500 9.500 42.500 9.500 51.100 6.900 51.100 6.900 41.100 0.700 41.100 0.700 7.900 3.300 7.900 ;
      POLYGON 6.500 27.900 6.400 27.900 6.400 31.300 3.900 31.300 3.900 25.100 6.500 25.100 ;
      POLYGON 13.600 27.900 11.800 27.900 11.800 26.500 8.700 26.500 8.700 23.900 13.600 23.900 ;
      POLYGON 13.500 13.700 13.500 10.500 12.700 10.500 12.700 7.900 15.300 7.900 15.300 11.900 23.600 11.900 23.600 10.500 22.900 10.500 22.900 7.900 25.500 7.900 25.500 10.500 25.400 10.500 25.400 27.900 23.600 27.900 23.600 13.700 ;
  END
END XOR2

END LIBRARY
